VERSION 5.8 ;
BUSBITCHARS "[]" ;
DIVIDERCHAR "/" ;
UNITS
    DATABASE MICRONS 1000 ;
END UNITS

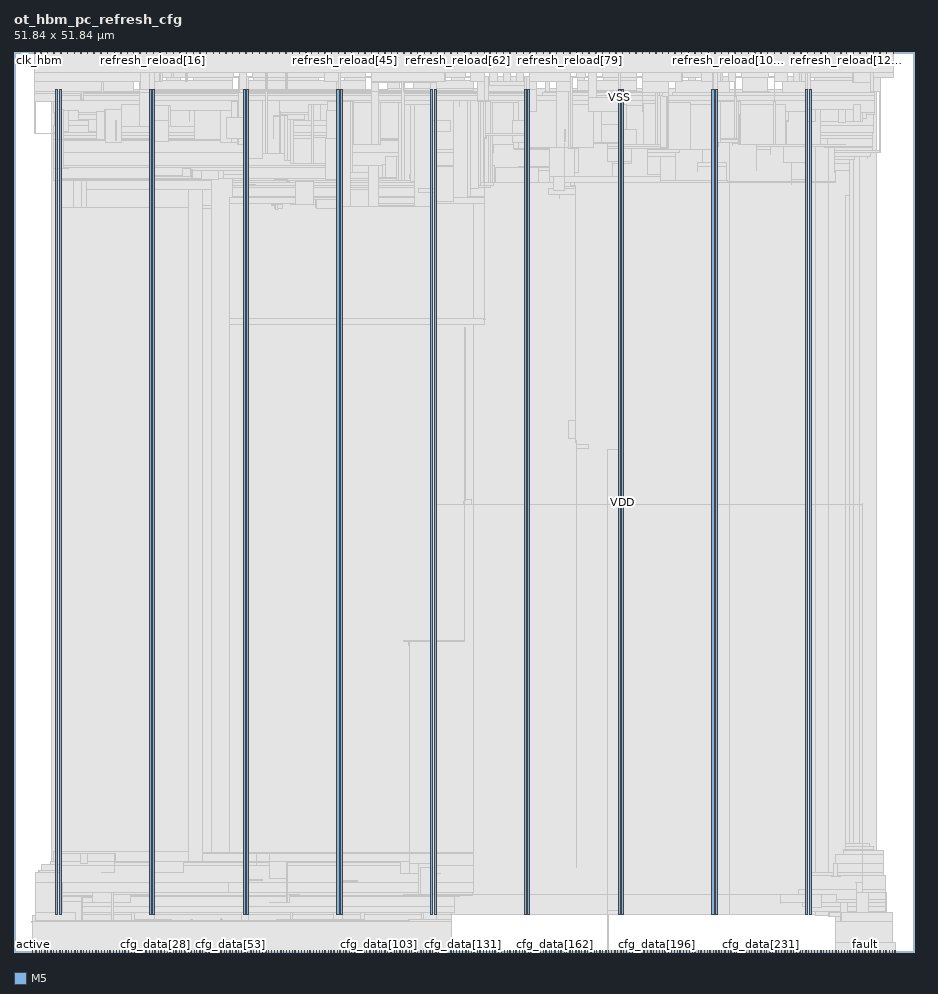
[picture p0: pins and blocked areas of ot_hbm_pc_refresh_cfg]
MACRO ot_hbm_pc_refresh_cfg
  FOREIGN ot_hbm_pc_refresh_cfg 0 0 ;
  CLASS BLOCK ;
  SIZE 51.84 BY 51.84 ;
  PIN active
    DIRECTION OUTPUT ;
    USE SIGNAL ;
    PORT
      LAYER M5 ;
        RECT  1.056 0 1.08 0.084 ;
    END
  END active
  PIN cfg_addr[0]
    DIRECTION INPUT ;
    USE SIGNAL ;
    PORT
      LAYER M5 ;
        RECT  1.248 0 1.272 0.084 ;
    END
  END cfg_addr[0]
  PIN cfg_addr[10]
    DIRECTION INPUT ;
    USE SIGNAL ;
    PORT
      LAYER M5 ;
        RECT  2.976 0 3 0.084 ;
    END
  END cfg_addr[10]
  PIN cfg_addr[11]
    DIRECTION INPUT ;
    USE SIGNAL ;
    PORT
      LAYER M5 ;
        RECT  3.12 0 3.144 0.084 ;
    END
  END cfg_addr[11]
  PIN cfg_addr[1]
    DIRECTION INPUT ;
    USE SIGNAL ;
    PORT
      LAYER M5 ;
        RECT  1.44 0 1.464 0.084 ;
    END
  END cfg_addr[1]
  PIN cfg_addr[2]
    DIRECTION INPUT ;
    USE SIGNAL ;
    PORT
      LAYER M5 ;
        RECT  1.584 0 1.608 0.084 ;
    END
  END cfg_addr[2]
  PIN cfg_addr[3]
    DIRECTION INPUT ;
    USE SIGNAL ;
    PORT
      LAYER M5 ;
        RECT  1.776 0 1.8 0.084 ;
    END
  END cfg_addr[3]
  PIN cfg_addr[4]
    DIRECTION INPUT ;
    USE SIGNAL ;
    PORT
      LAYER M5 ;
        RECT  1.92 0 1.944 0.084 ;
    END
  END cfg_addr[4]
  PIN cfg_addr[5]
    DIRECTION INPUT ;
    USE SIGNAL ;
    PORT
      LAYER M5 ;
        RECT  2.112 0 2.136 0.084 ;
    END
  END cfg_addr[5]
  PIN cfg_addr[6]
    DIRECTION INPUT ;
    USE SIGNAL ;
    PORT
      LAYER M5 ;
        RECT  2.256 0 2.28 0.084 ;
    END
  END cfg_addr[6]
  PIN cfg_addr[7]
    DIRECTION INPUT ;
    USE SIGNAL ;
    PORT
      LAYER M5 ;
        RECT  2.448 0 2.472 0.084 ;
    END
  END cfg_addr[7]
  PIN cfg_addr[8]
    DIRECTION INPUT ;
    USE SIGNAL ;
    PORT
      LAYER M5 ;
        RECT  2.64 0 2.664 0.084 ;
    END
  END cfg_addr[8]
  PIN cfg_addr[9]
    DIRECTION INPUT ;
    USE SIGNAL ;
    PORT
      LAYER M5 ;
        RECT  2.784 0 2.808 0.084 ;
    END
  END cfg_addr[9]
  PIN cfg_data[0]
    DIRECTION INPUT ;
    USE SIGNAL ;
    PORT
      LAYER M5 ;
        RECT  3.312 0 3.336 0.084 ;
    END
  END cfg_data[0]
  PIN cfg_data[100]
    DIRECTION INPUT ;
    USE SIGNAL ;
    PORT
      LAYER M5 ;
        RECT  20.496 0 20.52 0.084 ;
    END
  END cfg_data[100]
  PIN cfg_data[101]
    DIRECTION INPUT ;
    USE SIGNAL ;
    PORT
      LAYER M5 ;
        RECT  20.688 0 20.712 0.084 ;
    END
  END cfg_data[101]
  PIN cfg_data[102]
    DIRECTION INPUT ;
    USE SIGNAL ;
    PORT
      LAYER M5 ;
        RECT  20.832 0 20.856 0.084 ;
    END
  END cfg_data[102]
  PIN cfg_data[103]
    DIRECTION INPUT ;
    USE SIGNAL ;
    PORT
      LAYER M5 ;
        RECT  21.024 0 21.048 0.084 ;
    END
  END cfg_data[103]
  PIN cfg_data[104]
    DIRECTION INPUT ;
    USE SIGNAL ;
    PORT
      LAYER M5 ;
        RECT  21.168 0 21.192 0.084 ;
    END
  END cfg_data[104]
  PIN cfg_data[105]
    DIRECTION INPUT ;
    USE SIGNAL ;
    PORT
      LAYER M5 ;
        RECT  21.36 0 21.384 0.084 ;
    END
  END cfg_data[105]
  PIN cfg_data[106]
    DIRECTION INPUT ;
    USE SIGNAL ;
    PORT
      LAYER M5 ;
        RECT  21.504 0 21.528 0.084 ;
    END
  END cfg_data[106]
  PIN cfg_data[107]
    DIRECTION INPUT ;
    USE SIGNAL ;
    PORT
      LAYER M5 ;
        RECT  21.696 0 21.72 0.084 ;
    END
  END cfg_data[107]
  PIN cfg_data[108]
    DIRECTION INPUT ;
    USE SIGNAL ;
    PORT
      LAYER M5 ;
        RECT  21.888 0 21.912 0.084 ;
    END
  END cfg_data[108]
  PIN cfg_data[109]
    DIRECTION INPUT ;
    USE SIGNAL ;
    PORT
      LAYER M5 ;
        RECT  22.032 0 22.056 0.084 ;
    END
  END cfg_data[109]
  PIN cfg_data[10]
    DIRECTION INPUT ;
    USE SIGNAL ;
    PORT
      LAYER M5 ;
        RECT  5.04 0 5.064 0.084 ;
    END
  END cfg_data[10]
  PIN cfg_data[110]
    DIRECTION INPUT ;
    USE SIGNAL ;
    PORT
      LAYER M5 ;
        RECT  22.224 0 22.248 0.084 ;
    END
  END cfg_data[110]
  PIN cfg_data[111]
    DIRECTION INPUT ;
    USE SIGNAL ;
    PORT
      LAYER M5 ;
        RECT  22.368 0 22.392 0.084 ;
    END
  END cfg_data[111]
  PIN cfg_data[112]
    DIRECTION INPUT ;
    USE SIGNAL ;
    PORT
      LAYER M5 ;
        RECT  22.56 0 22.584 0.084 ;
    END
  END cfg_data[112]
  PIN cfg_data[113]
    DIRECTION INPUT ;
    USE SIGNAL ;
    PORT
      LAYER M5 ;
        RECT  22.752 0 22.776 0.084 ;
    END
  END cfg_data[113]
  PIN cfg_data[114]
    DIRECTION INPUT ;
    USE SIGNAL ;
    PORT
      LAYER M5 ;
        RECT  22.896 0 22.92 0.084 ;
    END
  END cfg_data[114]
  PIN cfg_data[115]
    DIRECTION INPUT ;
    USE SIGNAL ;
    PORT
      LAYER M5 ;
        RECT  23.088 0 23.112 0.084 ;
    END
  END cfg_data[115]
  PIN cfg_data[116]
    DIRECTION INPUT ;
    USE SIGNAL ;
    PORT
      LAYER M5 ;
        RECT  23.232 0 23.256 0.084 ;
    END
  END cfg_data[116]
  PIN cfg_data[117]
    DIRECTION INPUT ;
    USE SIGNAL ;
    PORT
      LAYER M5 ;
        RECT  23.424 0 23.448 0.084 ;
    END
  END cfg_data[117]
  PIN cfg_data[118]
    DIRECTION INPUT ;
    USE SIGNAL ;
    PORT
      LAYER M5 ;
        RECT  23.568 0 23.592 0.084 ;
    END
  END cfg_data[118]
  PIN cfg_data[119]
    DIRECTION INPUT ;
    USE SIGNAL ;
    PORT
      LAYER M5 ;
        RECT  23.76 0 23.784 0.084 ;
    END
  END cfg_data[119]
  PIN cfg_data[11]
    DIRECTION INPUT ;
    USE SIGNAL ;
    PORT
      LAYER M5 ;
        RECT  5.184 0 5.208 0.084 ;
    END
  END cfg_data[11]
  PIN cfg_data[120]
    DIRECTION INPUT ;
    USE SIGNAL ;
    PORT
      LAYER M5 ;
        RECT  23.952 0 23.976 0.084 ;
    END
  END cfg_data[120]
  PIN cfg_data[121]
    DIRECTION INPUT ;
    USE SIGNAL ;
    PORT
      LAYER M5 ;
        RECT  24.096 0 24.12 0.084 ;
    END
  END cfg_data[121]
  PIN cfg_data[122]
    DIRECTION INPUT ;
    USE SIGNAL ;
    PORT
      LAYER M5 ;
        RECT  24.288 0 24.312 0.084 ;
    END
  END cfg_data[122]
  PIN cfg_data[123]
    DIRECTION INPUT ;
    USE SIGNAL ;
    PORT
      LAYER M5 ;
        RECT  24.432 0 24.456 0.084 ;
    END
  END cfg_data[123]
  PIN cfg_data[124]
    DIRECTION INPUT ;
    USE SIGNAL ;
    PORT
      LAYER M5 ;
        RECT  24.624 0 24.648 0.084 ;
    END
  END cfg_data[124]
  PIN cfg_data[125]
    DIRECTION INPUT ;
    USE SIGNAL ;
    PORT
      LAYER M5 ;
        RECT  24.768 0 24.792 0.084 ;
    END
  END cfg_data[125]
  PIN cfg_data[126]
    DIRECTION INPUT ;
    USE SIGNAL ;
    PORT
      LAYER M5 ;
        RECT  24.96 0 24.984 0.084 ;
    END
  END cfg_data[126]
  PIN cfg_data[127]
    DIRECTION INPUT ;
    USE SIGNAL ;
    PORT
      LAYER M5 ;
        RECT  25.152 0 25.176 0.084 ;
    END
  END cfg_data[127]
  PIN cfg_data[128]
    DIRECTION INPUT ;
    USE SIGNAL ;
    PORT
      LAYER M5 ;
        RECT  25.296 0 25.32 0.084 ;
    END
  END cfg_data[128]
  PIN cfg_data[129]
    DIRECTION INPUT ;
    USE SIGNAL ;
    PORT
      LAYER M5 ;
        RECT  25.488 0 25.512 0.084 ;
    END
  END cfg_data[129]
  PIN cfg_data[12]
    DIRECTION INPUT ;
    USE SIGNAL ;
    PORT
      LAYER M5 ;
        RECT  5.376 0 5.4 0.084 ;
    END
  END cfg_data[12]
  PIN cfg_data[130]
    DIRECTION INPUT ;
    USE SIGNAL ;
    PORT
      LAYER M5 ;
        RECT  25.632 0 25.656 0.084 ;
    END
  END cfg_data[130]
  PIN cfg_data[131]
    DIRECTION INPUT ;
    USE SIGNAL ;
    PORT
      LAYER M5 ;
        RECT  25.824 0 25.848 0.084 ;
    END
  END cfg_data[131]
  PIN cfg_data[132]
    DIRECTION INPUT ;
    USE SIGNAL ;
    PORT
      LAYER M5 ;
        RECT  26.016 0 26.04 0.084 ;
    END
  END cfg_data[132]
  PIN cfg_data[133]
    DIRECTION INPUT ;
    USE SIGNAL ;
    PORT
      LAYER M5 ;
        RECT  26.16 0 26.184 0.084 ;
    END
  END cfg_data[133]
  PIN cfg_data[134]
    DIRECTION INPUT ;
    USE SIGNAL ;
    PORT
      LAYER M5 ;
        RECT  26.352 0 26.376 0.084 ;
    END
  END cfg_data[134]
  PIN cfg_data[135]
    DIRECTION INPUT ;
    USE SIGNAL ;
    PORT
      LAYER M5 ;
        RECT  26.496 0 26.52 0.084 ;
    END
  END cfg_data[135]
  PIN cfg_data[136]
    DIRECTION INPUT ;
    USE SIGNAL ;
    PORT
      LAYER M5 ;
        RECT  26.688 0 26.712 0.084 ;
    END
  END cfg_data[136]
  PIN cfg_data[137]
    DIRECTION INPUT ;
    USE SIGNAL ;
    PORT
      LAYER M5 ;
        RECT  26.832 0 26.856 0.084 ;
    END
  END cfg_data[137]
  PIN cfg_data[138]
    DIRECTION INPUT ;
    USE SIGNAL ;
    PORT
      LAYER M5 ;
        RECT  27.024 0 27.048 0.084 ;
    END
  END cfg_data[138]
  PIN cfg_data[139]
    DIRECTION INPUT ;
    USE SIGNAL ;
    PORT
      LAYER M5 ;
        RECT  27.216 0 27.24 0.084 ;
    END
  END cfg_data[139]
  PIN cfg_data[13]
    DIRECTION INPUT ;
    USE SIGNAL ;
    PORT
      LAYER M5 ;
        RECT  5.52 0 5.544 0.084 ;
    END
  END cfg_data[13]
  PIN cfg_data[140]
    DIRECTION INPUT ;
    USE SIGNAL ;
    PORT
      LAYER M5 ;
        RECT  27.36 0 27.384 0.084 ;
    END
  END cfg_data[140]
  PIN cfg_data[141]
    DIRECTION INPUT ;
    USE SIGNAL ;
    PORT
      LAYER M5 ;
        RECT  27.552 0 27.576 0.084 ;
    END
  END cfg_data[141]
  PIN cfg_data[142]
    DIRECTION INPUT ;
    USE SIGNAL ;
    PORT
      LAYER M5 ;
        RECT  27.696 0 27.72 0.084 ;
    END
  END cfg_data[142]
  PIN cfg_data[143]
    DIRECTION INPUT ;
    USE SIGNAL ;
    PORT
      LAYER M5 ;
        RECT  27.888 0 27.912 0.084 ;
    END
  END cfg_data[143]
  PIN cfg_data[144]
    DIRECTION INPUT ;
    USE SIGNAL ;
    PORT
      LAYER M5 ;
        RECT  28.08 0 28.104 0.084 ;
    END
  END cfg_data[144]
  PIN cfg_data[145]
    DIRECTION INPUT ;
    USE SIGNAL ;
    PORT
      LAYER M5 ;
        RECT  28.224 0 28.248 0.084 ;
    END
  END cfg_data[145]
  PIN cfg_data[146]
    DIRECTION INPUT ;
    USE SIGNAL ;
    PORT
      LAYER M5 ;
        RECT  28.416 0 28.44 0.084 ;
    END
  END cfg_data[146]
  PIN cfg_data[147]
    DIRECTION INPUT ;
    USE SIGNAL ;
    PORT
      LAYER M5 ;
        RECT  28.56 0 28.584 0.084 ;
    END
  END cfg_data[147]
  PIN cfg_data[148]
    DIRECTION INPUT ;
    USE SIGNAL ;
    PORT
      LAYER M5 ;
        RECT  28.752 0 28.776 0.084 ;
    END
  END cfg_data[148]
  PIN cfg_data[149]
    DIRECTION INPUT ;
    USE SIGNAL ;
    PORT
      LAYER M5 ;
        RECT  28.896 0 28.92 0.084 ;
    END
  END cfg_data[149]
  PIN cfg_data[14]
    DIRECTION INPUT ;
    USE SIGNAL ;
    PORT
      LAYER M5 ;
        RECT  5.712 0 5.736 0.084 ;
    END
  END cfg_data[14]
  PIN cfg_data[150]
    DIRECTION INPUT ;
    USE SIGNAL ;
    PORT
      LAYER M5 ;
        RECT  29.088 0 29.112 0.084 ;
    END
  END cfg_data[150]
  PIN cfg_data[151]
    DIRECTION INPUT ;
    USE SIGNAL ;
    PORT
      LAYER M5 ;
        RECT  29.28 0 29.304 0.084 ;
    END
  END cfg_data[151]
  PIN cfg_data[152]
    DIRECTION INPUT ;
    USE SIGNAL ;
    PORT
      LAYER M5 ;
        RECT  29.424 0 29.448 0.084 ;
    END
  END cfg_data[152]
  PIN cfg_data[153]
    DIRECTION INPUT ;
    USE SIGNAL ;
    PORT
      LAYER M5 ;
        RECT  29.616 0 29.64 0.084 ;
    END
  END cfg_data[153]
  PIN cfg_data[154]
    DIRECTION INPUT ;
    USE SIGNAL ;
    PORT
      LAYER M5 ;
        RECT  29.76 0 29.784 0.084 ;
    END
  END cfg_data[154]
  PIN cfg_data[155]
    DIRECTION INPUT ;
    USE SIGNAL ;
    PORT
      LAYER M5 ;
        RECT  29.952 0 29.976 0.084 ;
    END
  END cfg_data[155]
  PIN cfg_data[156]
    DIRECTION INPUT ;
    USE SIGNAL ;
    PORT
      LAYER M5 ;
        RECT  30.096 0 30.12 0.084 ;
    END
  END cfg_data[156]
  PIN cfg_data[157]
    DIRECTION INPUT ;
    USE SIGNAL ;
    PORT
      LAYER M5 ;
        RECT  30.288 0 30.312 0.084 ;
    END
  END cfg_data[157]
  PIN cfg_data[158]
    DIRECTION INPUT ;
    USE SIGNAL ;
    PORT
      LAYER M5 ;
        RECT  30.48 0 30.504 0.084 ;
    END
  END cfg_data[158]
  PIN cfg_data[159]
    DIRECTION INPUT ;
    USE SIGNAL ;
    PORT
      LAYER M5 ;
        RECT  30.624 0 30.648 0.084 ;
    END
  END cfg_data[159]
  PIN cfg_data[15]
    DIRECTION INPUT ;
    USE SIGNAL ;
    PORT
      LAYER M5 ;
        RECT  5.904 0 5.928 0.084 ;
    END
  END cfg_data[15]
  PIN cfg_data[160]
    DIRECTION INPUT ;
    USE SIGNAL ;
    PORT
      LAYER M5 ;
        RECT  30.816 0 30.84 0.084 ;
    END
  END cfg_data[160]
  PIN cfg_data[161]
    DIRECTION INPUT ;
    USE SIGNAL ;
    PORT
      LAYER M5 ;
        RECT  30.96 0 30.984 0.084 ;
    END
  END cfg_data[161]
  PIN cfg_data[162]
    DIRECTION INPUT ;
    USE SIGNAL ;
    PORT
      LAYER M5 ;
        RECT  31.152 0 31.176 0.084 ;
    END
  END cfg_data[162]
  PIN cfg_data[163]
    DIRECTION INPUT ;
    USE SIGNAL ;
    PORT
      LAYER M5 ;
        RECT  31.344 0 31.368 0.084 ;
    END
  END cfg_data[163]
  PIN cfg_data[164]
    DIRECTION INPUT ;
    USE SIGNAL ;
    PORT
      LAYER M5 ;
        RECT  31.488 0 31.512 0.084 ;
    END
  END cfg_data[164]
  PIN cfg_data[165]
    DIRECTION INPUT ;
    USE SIGNAL ;
    PORT
      LAYER M5 ;
        RECT  31.68 0 31.704 0.084 ;
    END
  END cfg_data[165]
  PIN cfg_data[166]
    DIRECTION INPUT ;
    USE SIGNAL ;
    PORT
      LAYER M5 ;
        RECT  31.824 0 31.848 0.084 ;
    END
  END cfg_data[166]
  PIN cfg_data[167]
    DIRECTION INPUT ;
    USE SIGNAL ;
    PORT
      LAYER M5 ;
        RECT  32.016 0 32.04 0.084 ;
    END
  END cfg_data[167]
  PIN cfg_data[168]
    DIRECTION INPUT ;
    USE SIGNAL ;
    PORT
      LAYER M5 ;
        RECT  32.16 0 32.184 0.084 ;
    END
  END cfg_data[168]
  PIN cfg_data[169]
    DIRECTION INPUT ;
    USE SIGNAL ;
    PORT
      LAYER M5 ;
        RECT  32.352 0 32.376 0.084 ;
    END
  END cfg_data[169]
  PIN cfg_data[16]
    DIRECTION INPUT ;
    USE SIGNAL ;
    PORT
      LAYER M5 ;
        RECT  6.048 0 6.072 0.084 ;
    END
  END cfg_data[16]
  PIN cfg_data[170]
    DIRECTION INPUT ;
    USE SIGNAL ;
    PORT
      LAYER M5 ;
        RECT  32.544 0 32.568 0.084 ;
    END
  END cfg_data[170]
  PIN cfg_data[171]
    DIRECTION INPUT ;
    USE SIGNAL ;
    PORT
      LAYER M5 ;
        RECT  32.688 0 32.712 0.084 ;
    END
  END cfg_data[171]
  PIN cfg_data[172]
    DIRECTION INPUT ;
    USE SIGNAL ;
    PORT
      LAYER M5 ;
        RECT  32.88 0 32.904 0.084 ;
    END
  END cfg_data[172]
  PIN cfg_data[173]
    DIRECTION INPUT ;
    USE SIGNAL ;
    PORT
      LAYER M5 ;
        RECT  33.024 0 33.048 0.084 ;
    END
  END cfg_data[173]
  PIN cfg_data[174]
    DIRECTION INPUT ;
    USE SIGNAL ;
    PORT
      LAYER M5 ;
        RECT  33.216 0 33.24 0.084 ;
    END
  END cfg_data[174]
  PIN cfg_data[175]
    DIRECTION INPUT ;
    USE SIGNAL ;
    PORT
      LAYER M5 ;
        RECT  33.408 0 33.432 0.084 ;
    END
  END cfg_data[175]
  PIN cfg_data[176]
    DIRECTION INPUT ;
    USE SIGNAL ;
    PORT
      LAYER M5 ;
        RECT  33.552 0 33.576 0.084 ;
    END
  END cfg_data[176]
  PIN cfg_data[177]
    DIRECTION INPUT ;
    USE SIGNAL ;
    PORT
      LAYER M5 ;
        RECT  33.744 0 33.768 0.084 ;
    END
  END cfg_data[177]
  PIN cfg_data[178]
    DIRECTION INPUT ;
    USE SIGNAL ;
    PORT
      LAYER M5 ;
        RECT  33.888 0 33.912 0.084 ;
    END
  END cfg_data[178]
  PIN cfg_data[179]
    DIRECTION INPUT ;
    USE SIGNAL ;
    PORT
      LAYER M5 ;
        RECT  34.08 0 34.104 0.084 ;
    END
  END cfg_data[179]
  PIN cfg_data[17]
    DIRECTION INPUT ;
    USE SIGNAL ;
    PORT
      LAYER M5 ;
        RECT  6.24 0 6.264 0.084 ;
    END
  END cfg_data[17]
  PIN cfg_data[180]
    DIRECTION INPUT ;
    USE SIGNAL ;
    PORT
      LAYER M5 ;
        RECT  34.224 0 34.248 0.084 ;
    END
  END cfg_data[180]
  PIN cfg_data[181]
    DIRECTION INPUT ;
    USE SIGNAL ;
    PORT
      LAYER M5 ;
        RECT  34.416 0 34.44 0.084 ;
    END
  END cfg_data[181]
  PIN cfg_data[182]
    DIRECTION INPUT ;
    USE SIGNAL ;
    PORT
      LAYER M5 ;
        RECT  34.608 0 34.632 0.084 ;
    END
  END cfg_data[182]
  PIN cfg_data[183]
    DIRECTION INPUT ;
    USE SIGNAL ;
    PORT
      LAYER M5 ;
        RECT  34.752 0 34.776 0.084 ;
    END
  END cfg_data[183]
  PIN cfg_data[184]
    DIRECTION INPUT ;
    USE SIGNAL ;
    PORT
      LAYER M5 ;
        RECT  34.944 0 34.968 0.084 ;
    END
  END cfg_data[184]
  PIN cfg_data[185]
    DIRECTION INPUT ;
    USE SIGNAL ;
    PORT
      LAYER M5 ;
        RECT  35.088 0 35.112 0.084 ;
    END
  END cfg_data[185]
  PIN cfg_data[186]
    DIRECTION INPUT ;
    USE SIGNAL ;
    PORT
      LAYER M5 ;
        RECT  35.28 0 35.304 0.084 ;
    END
  END cfg_data[186]
  PIN cfg_data[187]
    DIRECTION INPUT ;
    USE SIGNAL ;
    PORT
      LAYER M5 ;
        RECT  35.424 0 35.448 0.084 ;
    END
  END cfg_data[187]
  PIN cfg_data[188]
    DIRECTION INPUT ;
    USE SIGNAL ;
    PORT
      LAYER M5 ;
        RECT  35.616 0 35.64 0.084 ;
    END
  END cfg_data[188]
  PIN cfg_data[189]
    DIRECTION INPUT ;
    USE SIGNAL ;
    PORT
      LAYER M5 ;
        RECT  35.808 0 35.832 0.084 ;
    END
  END cfg_data[189]
  PIN cfg_data[18]
    DIRECTION INPUT ;
    USE SIGNAL ;
    PORT
      LAYER M5 ;
        RECT  6.384 0 6.408 0.084 ;
    END
  END cfg_data[18]
  PIN cfg_data[190]
    DIRECTION INPUT ;
    USE SIGNAL ;
    PORT
      LAYER M5 ;
        RECT  35.952 0 35.976 0.084 ;
    END
  END cfg_data[190]
  PIN cfg_data[191]
    DIRECTION INPUT ;
    USE SIGNAL ;
    PORT
      LAYER M5 ;
        RECT  36.144 0 36.168 0.084 ;
    END
  END cfg_data[191]
  PIN cfg_data[192]
    DIRECTION INPUT ;
    USE SIGNAL ;
    PORT
      LAYER M5 ;
        RECT  36.288 0 36.312 0.084 ;
    END
  END cfg_data[192]
  PIN cfg_data[193]
    DIRECTION INPUT ;
    USE SIGNAL ;
    PORT
      LAYER M5 ;
        RECT  36.48 0 36.504 0.084 ;
    END
  END cfg_data[193]
  PIN cfg_data[194]
    DIRECTION INPUT ;
    USE SIGNAL ;
    PORT
      LAYER M5 ;
        RECT  36.672 0 36.696 0.084 ;
    END
  END cfg_data[194]
  PIN cfg_data[195]
    DIRECTION INPUT ;
    USE SIGNAL ;
    PORT
      LAYER M5 ;
        RECT  36.816 0 36.84 0.084 ;
    END
  END cfg_data[195]
  PIN cfg_data[196]
    DIRECTION INPUT ;
    USE SIGNAL ;
    PORT
      LAYER M5 ;
        RECT  37.008 0 37.032 0.084 ;
    END
  END cfg_data[196]
  PIN cfg_data[197]
    DIRECTION INPUT ;
    USE SIGNAL ;
    PORT
      LAYER M5 ;
        RECT  37.152 0 37.176 0.084 ;
    END
  END cfg_data[197]
  PIN cfg_data[198]
    DIRECTION INPUT ;
    USE SIGNAL ;
    PORT
      LAYER M5 ;
        RECT  37.344 0 37.368 0.084 ;
    END
  END cfg_data[198]
  PIN cfg_data[199]
    DIRECTION INPUT ;
    USE SIGNAL ;
    PORT
      LAYER M5 ;
        RECT  37.488 0 37.512 0.084 ;
    END
  END cfg_data[199]
  PIN cfg_data[19]
    DIRECTION INPUT ;
    USE SIGNAL ;
    PORT
      LAYER M5 ;
        RECT  6.576 0 6.6 0.084 ;
    END
  END cfg_data[19]
  PIN cfg_data[1]
    DIRECTION INPUT ;
    USE SIGNAL ;
    PORT
      LAYER M5 ;
        RECT  3.504 0 3.528 0.084 ;
    END
  END cfg_data[1]
  PIN cfg_data[200]
    DIRECTION INPUT ;
    USE SIGNAL ;
    PORT
      LAYER M5 ;
        RECT  37.68 0 37.704 0.084 ;
    END
  END cfg_data[200]
  PIN cfg_data[201]
    DIRECTION INPUT ;
    USE SIGNAL ;
    PORT
      LAYER M5 ;
        RECT  37.872 0 37.896 0.084 ;
    END
  END cfg_data[201]
  PIN cfg_data[202]
    DIRECTION INPUT ;
    USE SIGNAL ;
    PORT
      LAYER M5 ;
        RECT  38.016 0 38.04 0.084 ;
    END
  END cfg_data[202]
  PIN cfg_data[203]
    DIRECTION INPUT ;
    USE SIGNAL ;
    PORT
      LAYER M5 ;
        RECT  38.208 0 38.232 0.084 ;
    END
  END cfg_data[203]
  PIN cfg_data[204]
    DIRECTION INPUT ;
    USE SIGNAL ;
    PORT
      LAYER M5 ;
        RECT  38.352 0 38.376 0.084 ;
    END
  END cfg_data[204]
  PIN cfg_data[205]
    DIRECTION INPUT ;
    USE SIGNAL ;
    PORT
      LAYER M5 ;
        RECT  38.544 0 38.568 0.084 ;
    END
  END cfg_data[205]
  PIN cfg_data[206]
    DIRECTION INPUT ;
    USE SIGNAL ;
    PORT
      LAYER M5 ;
        RECT  38.736 0 38.76 0.084 ;
    END
  END cfg_data[206]
  PIN cfg_data[207]
    DIRECTION INPUT ;
    USE SIGNAL ;
    PORT
      LAYER M5 ;
        RECT  38.88 0 38.904 0.084 ;
    END
  END cfg_data[207]
  PIN cfg_data[208]
    DIRECTION INPUT ;
    USE SIGNAL ;
    PORT
      LAYER M5 ;
        RECT  39.072 0 39.096 0.084 ;
    END
  END cfg_data[208]
  PIN cfg_data[209]
    DIRECTION INPUT ;
    USE SIGNAL ;
    PORT
      LAYER M5 ;
        RECT  39.216 0 39.24 0.084 ;
    END
  END cfg_data[209]
  PIN cfg_data[20]
    DIRECTION INPUT ;
    USE SIGNAL ;
    PORT
      LAYER M5 ;
        RECT  6.768 0 6.792 0.084 ;
    END
  END cfg_data[20]
  PIN cfg_data[210]
    DIRECTION INPUT ;
    USE SIGNAL ;
    PORT
      LAYER M5 ;
        RECT  39.408 0 39.432 0.084 ;
    END
  END cfg_data[210]
  PIN cfg_data[211]
    DIRECTION INPUT ;
    USE SIGNAL ;
    PORT
      LAYER M5 ;
        RECT  39.552 0 39.576 0.084 ;
    END
  END cfg_data[211]
  PIN cfg_data[212]
    DIRECTION INPUT ;
    USE SIGNAL ;
    PORT
      LAYER M5 ;
        RECT  39.744 0 39.768 0.084 ;
    END
  END cfg_data[212]
  PIN cfg_data[213]
    DIRECTION INPUT ;
    USE SIGNAL ;
    PORT
      LAYER M5 ;
        RECT  39.936 0 39.96 0.084 ;
    END
  END cfg_data[213]
  PIN cfg_data[214]
    DIRECTION INPUT ;
    USE SIGNAL ;
    PORT
      LAYER M5 ;
        RECT  40.08 0 40.104 0.084 ;
    END
  END cfg_data[214]
  PIN cfg_data[215]
    DIRECTION INPUT ;
    USE SIGNAL ;
    PORT
      LAYER M5 ;
        RECT  40.272 0 40.296 0.084 ;
    END
  END cfg_data[215]
  PIN cfg_data[216]
    DIRECTION INPUT ;
    USE SIGNAL ;
    PORT
      LAYER M5 ;
        RECT  40.416 0 40.44 0.084 ;
    END
  END cfg_data[216]
  PIN cfg_data[217]
    DIRECTION INPUT ;
    USE SIGNAL ;
    PORT
      LAYER M5 ;
        RECT  40.608 0 40.632 0.084 ;
    END
  END cfg_data[217]
  PIN cfg_data[218]
    DIRECTION INPUT ;
    USE SIGNAL ;
    PORT
      LAYER M5 ;
        RECT  40.752 0 40.776 0.084 ;
    END
  END cfg_data[218]
  PIN cfg_data[219]
    DIRECTION INPUT ;
    USE SIGNAL ;
    PORT
      LAYER M5 ;
        RECT  40.944 0 40.968 0.084 ;
    END
  END cfg_data[219]
  PIN cfg_data[21]
    DIRECTION INPUT ;
    USE SIGNAL ;
    PORT
      LAYER M5 ;
        RECT  6.912 0 6.936 0.084 ;
    END
  END cfg_data[21]
  PIN cfg_data[220]
    DIRECTION INPUT ;
    USE SIGNAL ;
    PORT
      LAYER M5 ;
        RECT  41.136 0 41.16 0.084 ;
    END
  END cfg_data[220]
  PIN cfg_data[221]
    DIRECTION INPUT ;
    USE SIGNAL ;
    PORT
      LAYER M5 ;
        RECT  41.28 0 41.304 0.084 ;
    END
  END cfg_data[221]
  PIN cfg_data[222]
    DIRECTION INPUT ;
    USE SIGNAL ;
    PORT
      LAYER M5 ;
        RECT  41.472 0 41.496 0.084 ;
    END
  END cfg_data[222]
  PIN cfg_data[223]
    DIRECTION INPUT ;
    USE SIGNAL ;
    PORT
      LAYER M5 ;
        RECT  41.616 0 41.64 0.084 ;
    END
  END cfg_data[223]
  PIN cfg_data[224]
    DIRECTION INPUT ;
    USE SIGNAL ;
    PORT
      LAYER M5 ;
        RECT  41.808 0 41.832 0.084 ;
    END
  END cfg_data[224]
  PIN cfg_data[225]
    DIRECTION INPUT ;
    USE SIGNAL ;
    PORT
      LAYER M5 ;
        RECT  42 0 42.024 0.084 ;
    END
  END cfg_data[225]
  PIN cfg_data[226]
    DIRECTION INPUT ;
    USE SIGNAL ;
    PORT
      LAYER M5 ;
        RECT  42.144 0 42.168 0.084 ;
    END
  END cfg_data[226]
  PIN cfg_data[227]
    DIRECTION INPUT ;
    USE SIGNAL ;
    PORT
      LAYER M5 ;
        RECT  42.336 0 42.36 0.084 ;
    END
  END cfg_data[227]
  PIN cfg_data[228]
    DIRECTION INPUT ;
    USE SIGNAL ;
    PORT
      LAYER M5 ;
        RECT  42.48 0 42.504 0.084 ;
    END
  END cfg_data[228]
  PIN cfg_data[229]
    DIRECTION INPUT ;
    USE SIGNAL ;
    PORT
      LAYER M5 ;
        RECT  42.672 0 42.696 0.084 ;
    END
  END cfg_data[229]
  PIN cfg_data[22]
    DIRECTION INPUT ;
    USE SIGNAL ;
    PORT
      LAYER M5 ;
        RECT  7.104 0 7.128 0.084 ;
    END
  END cfg_data[22]
  PIN cfg_data[230]
    DIRECTION INPUT ;
    USE SIGNAL ;
    PORT
      LAYER M5 ;
        RECT  42.816 0 42.84 0.084 ;
    END
  END cfg_data[230]
  PIN cfg_data[231]
    DIRECTION INPUT ;
    USE SIGNAL ;
    PORT
      LAYER M5 ;
        RECT  43.008 0 43.032 0.084 ;
    END
  END cfg_data[231]
  PIN cfg_data[232]
    DIRECTION INPUT ;
    USE SIGNAL ;
    PORT
      LAYER M5 ;
        RECT  43.2 0 43.224 0.084 ;
    END
  END cfg_data[232]
  PIN cfg_data[233]
    DIRECTION INPUT ;
    USE SIGNAL ;
    PORT
      LAYER M5 ;
        RECT  43.344 0 43.368 0.084 ;
    END
  END cfg_data[233]
  PIN cfg_data[234]
    DIRECTION INPUT ;
    USE SIGNAL ;
    PORT
      LAYER M5 ;
        RECT  43.536 0 43.56 0.084 ;
    END
  END cfg_data[234]
  PIN cfg_data[235]
    DIRECTION INPUT ;
    USE SIGNAL ;
    PORT
      LAYER M5 ;
        RECT  43.68 0 43.704 0.084 ;
    END
  END cfg_data[235]
  PIN cfg_data[236]
    DIRECTION INPUT ;
    USE SIGNAL ;
    PORT
      LAYER M5 ;
        RECT  43.872 0 43.896 0.084 ;
    END
  END cfg_data[236]
  PIN cfg_data[237]
    DIRECTION INPUT ;
    USE SIGNAL ;
    PORT
      LAYER M5 ;
        RECT  44.016 0 44.04 0.084 ;
    END
  END cfg_data[237]
  PIN cfg_data[238]
    DIRECTION INPUT ;
    USE SIGNAL ;
    PORT
      LAYER M5 ;
        RECT  44.208 0 44.232 0.084 ;
    END
  END cfg_data[238]
  PIN cfg_data[239]
    DIRECTION INPUT ;
    USE SIGNAL ;
    PORT
      LAYER M5 ;
        RECT  44.4 0 44.424 0.084 ;
    END
  END cfg_data[239]
  PIN cfg_data[23]
    DIRECTION INPUT ;
    USE SIGNAL ;
    PORT
      LAYER M5 ;
        RECT  7.248 0 7.272 0.084 ;
    END
  END cfg_data[23]
  PIN cfg_data[240]
    DIRECTION INPUT ;
    USE SIGNAL ;
    PORT
      LAYER M5 ;
        RECT  44.544 0 44.568 0.084 ;
    END
  END cfg_data[240]
  PIN cfg_data[241]
    DIRECTION INPUT ;
    USE SIGNAL ;
    PORT
      LAYER M5 ;
        RECT  44.736 0 44.76 0.084 ;
    END
  END cfg_data[241]
  PIN cfg_data[242]
    DIRECTION INPUT ;
    USE SIGNAL ;
    PORT
      LAYER M5 ;
        RECT  44.88 0 44.904 0.084 ;
    END
  END cfg_data[242]
  PIN cfg_data[243]
    DIRECTION INPUT ;
    USE SIGNAL ;
    PORT
      LAYER M5 ;
        RECT  45.072 0 45.096 0.084 ;
    END
  END cfg_data[243]
  PIN cfg_data[244]
    DIRECTION INPUT ;
    USE SIGNAL ;
    PORT
      LAYER M5 ;
        RECT  45.264 0 45.288 0.084 ;
    END
  END cfg_data[244]
  PIN cfg_data[245]
    DIRECTION INPUT ;
    USE SIGNAL ;
    PORT
      LAYER M5 ;
        RECT  45.408 0 45.432 0.084 ;
    END
  END cfg_data[245]
  PIN cfg_data[246]
    DIRECTION INPUT ;
    USE SIGNAL ;
    PORT
      LAYER M5 ;
        RECT  45.6 0 45.624 0.084 ;
    END
  END cfg_data[246]
  PIN cfg_data[247]
    DIRECTION INPUT ;
    USE SIGNAL ;
    PORT
      LAYER M5 ;
        RECT  45.744 0 45.768 0.084 ;
    END
  END cfg_data[247]
  PIN cfg_data[248]
    DIRECTION INPUT ;
    USE SIGNAL ;
    PORT
      LAYER M5 ;
        RECT  45.936 0 45.96 0.084 ;
    END
  END cfg_data[248]
  PIN cfg_data[249]
    DIRECTION INPUT ;
    USE SIGNAL ;
    PORT
      LAYER M5 ;
        RECT  46.08 0 46.104 0.084 ;
    END
  END cfg_data[249]
  PIN cfg_data[24]
    DIRECTION INPUT ;
    USE SIGNAL ;
    PORT
      LAYER M5 ;
        RECT  7.44 0 7.464 0.084 ;
    END
  END cfg_data[24]
  PIN cfg_data[250]
    DIRECTION INPUT ;
    USE SIGNAL ;
    PORT
      LAYER M5 ;
        RECT  46.272 0 46.296 0.084 ;
    END
  END cfg_data[250]
  PIN cfg_data[251]
    DIRECTION INPUT ;
    USE SIGNAL ;
    PORT
      LAYER M5 ;
        RECT  46.464 0 46.488 0.084 ;
    END
  END cfg_data[251]
  PIN cfg_data[252]
    DIRECTION INPUT ;
    USE SIGNAL ;
    PORT
      LAYER M5 ;
        RECT  46.608 0 46.632 0.084 ;
    END
  END cfg_data[252]
  PIN cfg_data[253]
    DIRECTION INPUT ;
    USE SIGNAL ;
    PORT
      LAYER M5 ;
        RECT  46.8 0 46.824 0.084 ;
    END
  END cfg_data[253]
  PIN cfg_data[254]
    DIRECTION INPUT ;
    USE SIGNAL ;
    PORT
      LAYER M5 ;
        RECT  46.944 0 46.968 0.084 ;
    END
  END cfg_data[254]
  PIN cfg_data[255]
    DIRECTION INPUT ;
    USE SIGNAL ;
    PORT
      LAYER M5 ;
        RECT  47.136 0 47.16 0.084 ;
    END
  END cfg_data[255]
  PIN cfg_data[25]
    DIRECTION INPUT ;
    USE SIGNAL ;
    PORT
      LAYER M5 ;
        RECT  7.584 0 7.608 0.084 ;
    END
  END cfg_data[25]
  PIN cfg_data[26]
    DIRECTION INPUT ;
    USE SIGNAL ;
    PORT
      LAYER M5 ;
        RECT  7.776 0 7.8 0.084 ;
    END
  END cfg_data[26]
  PIN cfg_data[27]
    DIRECTION INPUT ;
    USE SIGNAL ;
    PORT
      LAYER M5 ;
        RECT  7.968 0 7.992 0.084 ;
    END
  END cfg_data[27]
  PIN cfg_data[28]
    DIRECTION INPUT ;
    USE SIGNAL ;
    PORT
      LAYER M5 ;
        RECT  8.112 0 8.136 0.084 ;
    END
  END cfg_data[28]
  PIN cfg_data[29]
    DIRECTION INPUT ;
    USE SIGNAL ;
    PORT
      LAYER M5 ;
        RECT  8.304 0 8.328 0.084 ;
    END
  END cfg_data[29]
  PIN cfg_data[2]
    DIRECTION INPUT ;
    USE SIGNAL ;
    PORT
      LAYER M5 ;
        RECT  3.648 0 3.672 0.084 ;
    END
  END cfg_data[2]
  PIN cfg_data[30]
    DIRECTION INPUT ;
    USE SIGNAL ;
    PORT
      LAYER M5 ;
        RECT  8.448 0 8.472 0.084 ;
    END
  END cfg_data[30]
  PIN cfg_data[31]
    DIRECTION INPUT ;
    USE SIGNAL ;
    PORT
      LAYER M5 ;
        RECT  8.64 0 8.664 0.084 ;
    END
  END cfg_data[31]
  PIN cfg_data[32]
    DIRECTION INPUT ;
    USE SIGNAL ;
    PORT
      LAYER M5 ;
        RECT  8.832 0 8.856 0.084 ;
    END
  END cfg_data[32]
  PIN cfg_data[33]
    DIRECTION INPUT ;
    USE SIGNAL ;
    PORT
      LAYER M5 ;
        RECT  8.976 0 9 0.084 ;
    END
  END cfg_data[33]
  PIN cfg_data[34]
    DIRECTION INPUT ;
    USE SIGNAL ;
    PORT
      LAYER M5 ;
        RECT  9.168 0 9.192 0.084 ;
    END
  END cfg_data[34]
  PIN cfg_data[35]
    DIRECTION INPUT ;
    USE SIGNAL ;
    PORT
      LAYER M5 ;
        RECT  9.312 0 9.336 0.084 ;
    END
  END cfg_data[35]
  PIN cfg_data[36]
    DIRECTION INPUT ;
    USE SIGNAL ;
    PORT
      LAYER M5 ;
        RECT  9.504 0 9.528 0.084 ;
    END
  END cfg_data[36]
  PIN cfg_data[37]
    DIRECTION INPUT ;
    USE SIGNAL ;
    PORT
      LAYER M5 ;
        RECT  9.648 0 9.672 0.084 ;
    END
  END cfg_data[37]
  PIN cfg_data[38]
    DIRECTION INPUT ;
    USE SIGNAL ;
    PORT
      LAYER M5 ;
        RECT  9.84 0 9.864 0.084 ;
    END
  END cfg_data[38]
  PIN cfg_data[39]
    DIRECTION INPUT ;
    USE SIGNAL ;
    PORT
      LAYER M5 ;
        RECT  10.032 0 10.056 0.084 ;
    END
  END cfg_data[39]
  PIN cfg_data[3]
    DIRECTION INPUT ;
    USE SIGNAL ;
    PORT
      LAYER M5 ;
        RECT  3.84 0 3.864 0.084 ;
    END
  END cfg_data[3]
  PIN cfg_data[40]
    DIRECTION INPUT ;
    USE SIGNAL ;
    PORT
      LAYER M5 ;
        RECT  10.176 0 10.2 0.084 ;
    END
  END cfg_data[40]
  PIN cfg_data[41]
    DIRECTION INPUT ;
    USE SIGNAL ;
    PORT
      LAYER M5 ;
        RECT  10.368 0 10.392 0.084 ;
    END
  END cfg_data[41]
  PIN cfg_data[42]
    DIRECTION INPUT ;
    USE SIGNAL ;
    PORT
      LAYER M5 ;
        RECT  10.512 0 10.536 0.084 ;
    END
  END cfg_data[42]
  PIN cfg_data[43]
    DIRECTION INPUT ;
    USE SIGNAL ;
    PORT
      LAYER M5 ;
        RECT  10.704 0 10.728 0.084 ;
    END
  END cfg_data[43]
  PIN cfg_data[44]
    DIRECTION INPUT ;
    USE SIGNAL ;
    PORT
      LAYER M5 ;
        RECT  10.848 0 10.872 0.084 ;
    END
  END cfg_data[44]
  PIN cfg_data[45]
    DIRECTION INPUT ;
    USE SIGNAL ;
    PORT
      LAYER M5 ;
        RECT  11.04 0 11.064 0.084 ;
    END
  END cfg_data[45]
  PIN cfg_data[46]
    DIRECTION INPUT ;
    USE SIGNAL ;
    PORT
      LAYER M5 ;
        RECT  11.232 0 11.256 0.084 ;
    END
  END cfg_data[46]
  PIN cfg_data[47]
    DIRECTION INPUT ;
    USE SIGNAL ;
    PORT
      LAYER M5 ;
        RECT  11.376 0 11.4 0.084 ;
    END
  END cfg_data[47]
  PIN cfg_data[48]
    DIRECTION INPUT ;
    USE SIGNAL ;
    PORT
      LAYER M5 ;
        RECT  11.568 0 11.592 0.084 ;
    END
  END cfg_data[48]
  PIN cfg_data[49]
    DIRECTION INPUT ;
    USE SIGNAL ;
    PORT
      LAYER M5 ;
        RECT  11.712 0 11.736 0.084 ;
    END
  END cfg_data[49]
  PIN cfg_data[4]
    DIRECTION INPUT ;
    USE SIGNAL ;
    PORT
      LAYER M5 ;
        RECT  3.984 0 4.008 0.084 ;
    END
  END cfg_data[4]
  PIN cfg_data[50]
    DIRECTION INPUT ;
    USE SIGNAL ;
    PORT
      LAYER M5 ;
        RECT  11.904 0 11.928 0.084 ;
    END
  END cfg_data[50]
  PIN cfg_data[51]
    DIRECTION INPUT ;
    USE SIGNAL ;
    PORT
      LAYER M5 ;
        RECT  12.096 0 12.12 0.084 ;
    END
  END cfg_data[51]
  PIN cfg_data[52]
    DIRECTION INPUT ;
    USE SIGNAL ;
    PORT
      LAYER M5 ;
        RECT  12.24 0 12.264 0.084 ;
    END
  END cfg_data[52]
  PIN cfg_data[53]
    DIRECTION INPUT ;
    USE SIGNAL ;
    PORT
      LAYER M5 ;
        RECT  12.432 0 12.456 0.084 ;
    END
  END cfg_data[53]
  PIN cfg_data[54]
    DIRECTION INPUT ;
    USE SIGNAL ;
    PORT
      LAYER M5 ;
        RECT  12.576 0 12.6 0.084 ;
    END
  END cfg_data[54]
  PIN cfg_data[55]
    DIRECTION INPUT ;
    USE SIGNAL ;
    PORT
      LAYER M5 ;
        RECT  12.768 0 12.792 0.084 ;
    END
  END cfg_data[55]
  PIN cfg_data[56]
    DIRECTION INPUT ;
    USE SIGNAL ;
    PORT
      LAYER M5 ;
        RECT  12.912 0 12.936 0.084 ;
    END
  END cfg_data[56]
  PIN cfg_data[57]
    DIRECTION INPUT ;
    USE SIGNAL ;
    PORT
      LAYER M5 ;
        RECT  13.104 0 13.128 0.084 ;
    END
  END cfg_data[57]
  PIN cfg_data[58]
    DIRECTION INPUT ;
    USE SIGNAL ;
    PORT
      LAYER M5 ;
        RECT  13.296 0 13.32 0.084 ;
    END
  END cfg_data[58]
  PIN cfg_data[59]
    DIRECTION INPUT ;
    USE SIGNAL ;
    PORT
      LAYER M5 ;
        RECT  13.44 0 13.464 0.084 ;
    END
  END cfg_data[59]
  PIN cfg_data[5]
    DIRECTION INPUT ;
    USE SIGNAL ;
    PORT
      LAYER M5 ;
        RECT  4.176 0 4.2 0.084 ;
    END
  END cfg_data[5]
  PIN cfg_data[60]
    DIRECTION INPUT ;
    USE SIGNAL ;
    PORT
      LAYER M5 ;
        RECT  13.632 0 13.656 0.084 ;
    END
  END cfg_data[60]
  PIN cfg_data[61]
    DIRECTION INPUT ;
    USE SIGNAL ;
    PORT
      LAYER M5 ;
        RECT  13.776 0 13.8 0.084 ;
    END
  END cfg_data[61]
  PIN cfg_data[62]
    DIRECTION INPUT ;
    USE SIGNAL ;
    PORT
      LAYER M5 ;
        RECT  13.968 0 13.992 0.084 ;
    END
  END cfg_data[62]
  PIN cfg_data[63]
    DIRECTION INPUT ;
    USE SIGNAL ;
    PORT
      LAYER M5 ;
        RECT  14.112 0 14.136 0.084 ;
    END
  END cfg_data[63]
  PIN cfg_data[64]
    DIRECTION INPUT ;
    USE SIGNAL ;
    PORT
      LAYER M5 ;
        RECT  14.304 0 14.328 0.084 ;
    END
  END cfg_data[64]
  PIN cfg_data[65]
    DIRECTION INPUT ;
    USE SIGNAL ;
    PORT
      LAYER M5 ;
        RECT  14.496 0 14.52 0.084 ;
    END
  END cfg_data[65]
  PIN cfg_data[66]
    DIRECTION INPUT ;
    USE SIGNAL ;
    PORT
      LAYER M5 ;
        RECT  14.64 0 14.664 0.084 ;
    END
  END cfg_data[66]
  PIN cfg_data[67]
    DIRECTION INPUT ;
    USE SIGNAL ;
    PORT
      LAYER M5 ;
        RECT  14.832 0 14.856 0.084 ;
    END
  END cfg_data[67]
  PIN cfg_data[68]
    DIRECTION INPUT ;
    USE SIGNAL ;
    PORT
      LAYER M5 ;
        RECT  14.976 0 15 0.084 ;
    END
  END cfg_data[68]
  PIN cfg_data[69]
    DIRECTION INPUT ;
    USE SIGNAL ;
    PORT
      LAYER M5 ;
        RECT  15.168 0 15.192 0.084 ;
    END
  END cfg_data[69]
  PIN cfg_data[6]
    DIRECTION INPUT ;
    USE SIGNAL ;
    PORT
      LAYER M5 ;
        RECT  4.32 0 4.344 0.084 ;
    END
  END cfg_data[6]
  PIN cfg_data[70]
    DIRECTION INPUT ;
    USE SIGNAL ;
    PORT
      LAYER M5 ;
        RECT  15.36 0 15.384 0.084 ;
    END
  END cfg_data[70]
  PIN cfg_data[71]
    DIRECTION INPUT ;
    USE SIGNAL ;
    PORT
      LAYER M5 ;
        RECT  15.504 0 15.528 0.084 ;
    END
  END cfg_data[71]
  PIN cfg_data[72]
    DIRECTION INPUT ;
    USE SIGNAL ;
    PORT
      LAYER M5 ;
        RECT  15.696 0 15.72 0.084 ;
    END
  END cfg_data[72]
  PIN cfg_data[73]
    DIRECTION INPUT ;
    USE SIGNAL ;
    PORT
      LAYER M5 ;
        RECT  15.84 0 15.864 0.084 ;
    END
  END cfg_data[73]
  PIN cfg_data[74]
    DIRECTION INPUT ;
    USE SIGNAL ;
    PORT
      LAYER M5 ;
        RECT  16.032 0 16.056 0.084 ;
    END
  END cfg_data[74]
  PIN cfg_data[75]
    DIRECTION INPUT ;
    USE SIGNAL ;
    PORT
      LAYER M5 ;
        RECT  16.176 0 16.2 0.084 ;
    END
  END cfg_data[75]
  PIN cfg_data[76]
    DIRECTION INPUT ;
    USE SIGNAL ;
    PORT
      LAYER M5 ;
        RECT  16.368 0 16.392 0.084 ;
    END
  END cfg_data[76]
  PIN cfg_data[77]
    DIRECTION INPUT ;
    USE SIGNAL ;
    PORT
      LAYER M5 ;
        RECT  16.56 0 16.584 0.084 ;
    END
  END cfg_data[77]
  PIN cfg_data[78]
    DIRECTION INPUT ;
    USE SIGNAL ;
    PORT
      LAYER M5 ;
        RECT  16.704 0 16.728 0.084 ;
    END
  END cfg_data[78]
  PIN cfg_data[79]
    DIRECTION INPUT ;
    USE SIGNAL ;
    PORT
      LAYER M5 ;
        RECT  16.896 0 16.92 0.084 ;
    END
  END cfg_data[79]
  PIN cfg_data[7]
    DIRECTION INPUT ;
    USE SIGNAL ;
    PORT
      LAYER M5 ;
        RECT  4.512 0 4.536 0.084 ;
    END
  END cfg_data[7]
  PIN cfg_data[80]
    DIRECTION INPUT ;
    USE SIGNAL ;
    PORT
      LAYER M5 ;
        RECT  17.04 0 17.064 0.084 ;
    END
  END cfg_data[80]
  PIN cfg_data[81]
    DIRECTION INPUT ;
    USE SIGNAL ;
    PORT
      LAYER M5 ;
        RECT  17.232 0 17.256 0.084 ;
    END
  END cfg_data[81]
  PIN cfg_data[82]
    DIRECTION INPUT ;
    USE SIGNAL ;
    PORT
      LAYER M5 ;
        RECT  17.424 0 17.448 0.084 ;
    END
  END cfg_data[82]
  PIN cfg_data[83]
    DIRECTION INPUT ;
    USE SIGNAL ;
    PORT
      LAYER M5 ;
        RECT  17.568 0 17.592 0.084 ;
    END
  END cfg_data[83]
  PIN cfg_data[84]
    DIRECTION INPUT ;
    USE SIGNAL ;
    PORT
      LAYER M5 ;
        RECT  17.76 0 17.784 0.084 ;
    END
  END cfg_data[84]
  PIN cfg_data[85]
    DIRECTION INPUT ;
    USE SIGNAL ;
    PORT
      LAYER M5 ;
        RECT  17.904 0 17.928 0.084 ;
    END
  END cfg_data[85]
  PIN cfg_data[86]
    DIRECTION INPUT ;
    USE SIGNAL ;
    PORT
      LAYER M5 ;
        RECT  18.096 0 18.12 0.084 ;
    END
  END cfg_data[86]
  PIN cfg_data[87]
    DIRECTION INPUT ;
    USE SIGNAL ;
    PORT
      LAYER M5 ;
        RECT  18.24 0 18.264 0.084 ;
    END
  END cfg_data[87]
  PIN cfg_data[88]
    DIRECTION INPUT ;
    USE SIGNAL ;
    PORT
      LAYER M5 ;
        RECT  18.432 0 18.456 0.084 ;
    END
  END cfg_data[88]
  PIN cfg_data[89]
    DIRECTION INPUT ;
    USE SIGNAL ;
    PORT
      LAYER M5 ;
        RECT  18.624 0 18.648 0.084 ;
    END
  END cfg_data[89]
  PIN cfg_data[8]
    DIRECTION INPUT ;
    USE SIGNAL ;
    PORT
      LAYER M5 ;
        RECT  4.704 0 4.728 0.084 ;
    END
  END cfg_data[8]
  PIN cfg_data[90]
    DIRECTION INPUT ;
    USE SIGNAL ;
    PORT
      LAYER M5 ;
        RECT  18.768 0 18.792 0.084 ;
    END
  END cfg_data[90]
  PIN cfg_data[91]
    DIRECTION INPUT ;
    USE SIGNAL ;
    PORT
      LAYER M5 ;
        RECT  18.96 0 18.984 0.084 ;
    END
  END cfg_data[91]
  PIN cfg_data[92]
    DIRECTION INPUT ;
    USE SIGNAL ;
    PORT
      LAYER M5 ;
        RECT  19.104 0 19.128 0.084 ;
    END
  END cfg_data[92]
  PIN cfg_data[93]
    DIRECTION INPUT ;
    USE SIGNAL ;
    PORT
      LAYER M5 ;
        RECT  19.296 0 19.32 0.084 ;
    END
  END cfg_data[93]
  PIN cfg_data[94]
    DIRECTION INPUT ;
    USE SIGNAL ;
    PORT
      LAYER M5 ;
        RECT  19.44 0 19.464 0.084 ;
    END
  END cfg_data[94]
  PIN cfg_data[95]
    DIRECTION INPUT ;
    USE SIGNAL ;
    PORT
      LAYER M5 ;
        RECT  19.632 0 19.656 0.084 ;
    END
  END cfg_data[95]
  PIN cfg_data[96]
    DIRECTION INPUT ;
    USE SIGNAL ;
    PORT
      LAYER M5 ;
        RECT  19.824 0 19.848 0.084 ;
    END
  END cfg_data[96]
  PIN cfg_data[97]
    DIRECTION INPUT ;
    USE SIGNAL ;
    PORT
      LAYER M5 ;
        RECT  19.968 0 19.992 0.084 ;
    END
  END cfg_data[97]
  PIN cfg_data[98]
    DIRECTION INPUT ;
    USE SIGNAL ;
    PORT
      LAYER M5 ;
        RECT  20.16 0 20.184 0.084 ;
    END
  END cfg_data[98]
  PIN cfg_data[99]
    DIRECTION INPUT ;
    USE SIGNAL ;
    PORT
      LAYER M5 ;
        RECT  20.304 0 20.328 0.084 ;
    END
  END cfg_data[99]
  PIN cfg_data[9]
    DIRECTION INPUT ;
    USE SIGNAL ;
    PORT
      LAYER M5 ;
        RECT  4.848 0 4.872 0.084 ;
    END
  END cfg_data[9]
  PIN cfg_target[0]
    DIRECTION INPUT ;
    USE SIGNAL ;
    PORT
      LAYER M5 ;
        RECT  47.328 0 47.352 0.084 ;
    END
  END cfg_target[0]
  PIN cfg_target[1]
    DIRECTION INPUT ;
    USE SIGNAL ;
    PORT
      LAYER M5 ;
        RECT  47.472 0 47.496 0.084 ;
    END
  END cfg_target[1]
  PIN cfg_target[2]
    DIRECTION INPUT ;
    USE SIGNAL ;
    PORT
      LAYER M5 ;
        RECT  47.664 0 47.688 0.084 ;
    END
  END cfg_target[2]
  PIN cfg_target[3]
    DIRECTION INPUT ;
    USE SIGNAL ;
    PORT
      LAYER M5 ;
        RECT  47.808 0 47.832 0.084 ;
    END
  END cfg_target[3]
  PIN cfg_target[4]
    DIRECTION INPUT ;
    USE SIGNAL ;
    PORT
      LAYER M5 ;
        RECT  48 0 48.024 0.084 ;
    END
  END cfg_target[4]
  PIN cfg_target[5]
    DIRECTION INPUT ;
    USE SIGNAL ;
    PORT
      LAYER M5 ;
        RECT  48.144 0 48.168 0.084 ;
    END
  END cfg_target[5]
  PIN cfg_target[6]
    DIRECTION INPUT ;
    USE SIGNAL ;
    PORT
      LAYER M5 ;
        RECT  48.336 0 48.36 0.084 ;
    END
  END cfg_target[6]
  PIN cfg_target[7]
    DIRECTION INPUT ;
    USE SIGNAL ;
    PORT
      LAYER M5 ;
        RECT  48.528 0 48.552 0.084 ;
    END
  END cfg_target[7]
  PIN cfg_v
    DIRECTION INPUT ;
    USE SIGNAL ;
    PORT
      LAYER M5 ;
        RECT  48.672 0 48.696 0.084 ;
    END
  END cfg_v
  PIN clk
    DIRECTION INPUT ;
    USE SIGNAL ;
    PORT
      LAYER M5 ;
        RECT  48.864 0 48.888 0.084 ;
    END
  END clk
  PIN clk_hbm
    DIRECTION INPUT ;
    USE SIGNAL ;
    PORT
      LAYER M5 ;
        RECT  1.2 51.756 1.224 51.84 ;
    END
  END clk_hbm
  PIN fault
    DIRECTION OUTPUT ;
    USE SIGNAL ;
    PORT
      LAYER M5 ;
        RECT  49.008 0 49.032 0.084 ;
    END
  END fault
  PIN pc_rst_n
    DIRECTION OUTPUT ;
    USE SIGNAL ;
    PORT
      LAYER M5 ;
        RECT  1.536 51.756 1.56 51.84 ;
    END
  END pc_rst_n
  PIN ready
    DIRECTION OUTPUT ;
    USE SIGNAL ;
    PORT
      LAYER M5 ;
        RECT  49.2 0 49.224 0.084 ;
    END
  END ready
  PIN refresh_reload[0]
    DIRECTION OUTPUT ;
    USE SIGNAL ;
    PORT
      LAYER M5 ;
        RECT  1.92 51.756 1.944 51.84 ;
    END
  END refresh_reload[0]
  PIN refresh_reload[100]
    DIRECTION OUTPUT ;
    USE SIGNAL ;
    PORT
      LAYER M5 ;
        RECT  39.984 51.756 40.008 51.84 ;
    END
  END refresh_reload[100]
  PIN refresh_reload[101]
    DIRECTION OUTPUT ;
    USE SIGNAL ;
    PORT
      LAYER M5 ;
        RECT  40.368 51.756 40.392 51.84 ;
    END
  END refresh_reload[101]
  PIN refresh_reload[102]
    DIRECTION OUTPUT ;
    USE SIGNAL ;
    PORT
      LAYER M5 ;
        RECT  40.752 51.756 40.776 51.84 ;
    END
  END refresh_reload[102]
  PIN refresh_reload[103]
    DIRECTION OUTPUT ;
    USE SIGNAL ;
    PORT
      LAYER M5 ;
        RECT  41.136 51.756 41.16 51.84 ;
    END
  END refresh_reload[103]
  PIN refresh_reload[104]
    DIRECTION OUTPUT ;
    USE SIGNAL ;
    PORT
      LAYER M5 ;
        RECT  41.52 51.756 41.544 51.84 ;
    END
  END refresh_reload[104]
  PIN refresh_reload[105]
    DIRECTION OUTPUT ;
    USE SIGNAL ;
    PORT
      LAYER M5 ;
        RECT  41.904 51.756 41.928 51.84 ;
    END
  END refresh_reload[105]
  PIN refresh_reload[106]
    DIRECTION OUTPUT ;
    USE SIGNAL ;
    PORT
      LAYER M5 ;
        RECT  42.288 51.756 42.312 51.84 ;
    END
  END refresh_reload[106]
  PIN refresh_reload[107]
    DIRECTION OUTPUT ;
    USE SIGNAL ;
    PORT
      LAYER M5 ;
        RECT  42.672 51.756 42.696 51.84 ;
    END
  END refresh_reload[107]
  PIN refresh_reload[108]
    DIRECTION OUTPUT ;
    USE SIGNAL ;
    PORT
      LAYER M5 ;
        RECT  43.008 51.756 43.032 51.84 ;
    END
  END refresh_reload[108]
  PIN refresh_reload[109]
    DIRECTION OUTPUT ;
    USE SIGNAL ;
    PORT
      LAYER M5 ;
        RECT  43.392 51.756 43.416 51.84 ;
    END
  END refresh_reload[109]
  PIN refresh_reload[10]
    DIRECTION OUTPUT ;
    USE SIGNAL ;
    PORT
      LAYER M5 ;
        RECT  5.76 51.756 5.784 51.84 ;
    END
  END refresh_reload[10]
  PIN refresh_reload[110]
    DIRECTION OUTPUT ;
    USE SIGNAL ;
    PORT
      LAYER M5 ;
        RECT  43.776 51.756 43.8 51.84 ;
    END
  END refresh_reload[110]
  PIN refresh_reload[111]
    DIRECTION OUTPUT ;
    USE SIGNAL ;
    PORT
      LAYER M5 ;
        RECT  44.16 51.756 44.184 51.84 ;
    END
  END refresh_reload[111]
  PIN refresh_reload[112]
    DIRECTION OUTPUT ;
    USE SIGNAL ;
    PORT
      LAYER M5 ;
        RECT  44.544 51.756 44.568 51.84 ;
    END
  END refresh_reload[112]
  PIN refresh_reload[113]
    DIRECTION OUTPUT ;
    USE SIGNAL ;
    PORT
      LAYER M5 ;
        RECT  44.928 51.756 44.952 51.84 ;
    END
  END refresh_reload[113]
  PIN refresh_reload[114]
    DIRECTION OUTPUT ;
    USE SIGNAL ;
    PORT
      LAYER M5 ;
        RECT  45.312 51.756 45.336 51.84 ;
    END
  END refresh_reload[114]
  PIN refresh_reload[115]
    DIRECTION OUTPUT ;
    USE SIGNAL ;
    PORT
      LAYER M5 ;
        RECT  45.696 51.756 45.72 51.84 ;
    END
  END refresh_reload[115]
  PIN refresh_reload[116]
    DIRECTION OUTPUT ;
    USE SIGNAL ;
    PORT
      LAYER M5 ;
        RECT  46.08 51.756 46.104 51.84 ;
    END
  END refresh_reload[116]
  PIN refresh_reload[117]
    DIRECTION OUTPUT ;
    USE SIGNAL ;
    PORT
      LAYER M5 ;
        RECT  46.464 51.756 46.488 51.84 ;
    END
  END refresh_reload[117]
  PIN refresh_reload[118]
    DIRECTION OUTPUT ;
    USE SIGNAL ;
    PORT
      LAYER M5 ;
        RECT  46.848 51.756 46.872 51.84 ;
    END
  END refresh_reload[118]
  PIN refresh_reload[119]
    DIRECTION OUTPUT ;
    USE SIGNAL ;
    PORT
      LAYER M5 ;
        RECT  47.232 51.756 47.256 51.84 ;
    END
  END refresh_reload[119]
  PIN refresh_reload[11]
    DIRECTION OUTPUT ;
    USE SIGNAL ;
    PORT
      LAYER M5 ;
        RECT  6.144 51.756 6.168 51.84 ;
    END
  END refresh_reload[11]
  PIN refresh_reload[120]
    DIRECTION OUTPUT ;
    USE SIGNAL ;
    PORT
      LAYER M5 ;
        RECT  47.616 51.756 47.64 51.84 ;
    END
  END refresh_reload[120]
  PIN refresh_reload[121]
    DIRECTION OUTPUT ;
    USE SIGNAL ;
    PORT
      LAYER M5 ;
        RECT  47.952 51.756 47.976 51.84 ;
    END
  END refresh_reload[121]
  PIN refresh_reload[122]
    DIRECTION OUTPUT ;
    USE SIGNAL ;
    PORT
      LAYER M5 ;
        RECT  48.336 51.756 48.36 51.84 ;
    END
  END refresh_reload[122]
  PIN refresh_reload[123]
    DIRECTION OUTPUT ;
    USE SIGNAL ;
    PORT
      LAYER M5 ;
        RECT  48.72 51.756 48.744 51.84 ;
    END
  END refresh_reload[123]
  PIN refresh_reload[124]
    DIRECTION OUTPUT ;
    USE SIGNAL ;
    PORT
      LAYER M5 ;
        RECT  49.104 51.756 49.128 51.84 ;
    END
  END refresh_reload[124]
  PIN refresh_reload[125]
    DIRECTION OUTPUT ;
    USE SIGNAL ;
    PORT
      LAYER M5 ;
        RECT  49.488 51.756 49.512 51.84 ;
    END
  END refresh_reload[125]
  PIN refresh_reload[126]
    DIRECTION OUTPUT ;
    USE SIGNAL ;
    PORT
      LAYER M5 ;
        RECT  49.872 51.756 49.896 51.84 ;
    END
  END refresh_reload[126]
  PIN refresh_reload[127]
    DIRECTION OUTPUT ;
    USE SIGNAL ;
    PORT
      LAYER M5 ;
        RECT  50.256 51.756 50.28 51.84 ;
    END
  END refresh_reload[127]
  PIN refresh_reload[12]
    DIRECTION OUTPUT ;
    USE SIGNAL ;
    PORT
      LAYER M5 ;
        RECT  6.528 51.756 6.552 51.84 ;
    END
  END refresh_reload[12]
  PIN refresh_reload[13]
    DIRECTION OUTPUT ;
    USE SIGNAL ;
    PORT
      LAYER M5 ;
        RECT  6.864 51.756 6.888 51.84 ;
    END
  END refresh_reload[13]
  PIN refresh_reload[14]
    DIRECTION OUTPUT ;
    USE SIGNAL ;
    PORT
      LAYER M5 ;
        RECT  7.248 51.756 7.272 51.84 ;
    END
  END refresh_reload[14]
  PIN refresh_reload[15]
    DIRECTION OUTPUT ;
    USE SIGNAL ;
    PORT
      LAYER M5 ;
        RECT  7.632 51.756 7.656 51.84 ;
    END
  END refresh_reload[15]
  PIN refresh_reload[16]
    DIRECTION OUTPUT ;
    USE SIGNAL ;
    PORT
      LAYER M5 ;
        RECT  8.016 51.756 8.04 51.84 ;
    END
  END refresh_reload[16]
  PIN refresh_reload[17]
    DIRECTION OUTPUT ;
    USE SIGNAL ;
    PORT
      LAYER M5 ;
        RECT  8.4 51.756 8.424 51.84 ;
    END
  END refresh_reload[17]
  PIN refresh_reload[18]
    DIRECTION OUTPUT ;
    USE SIGNAL ;
    PORT
      LAYER M5 ;
        RECT  8.784 51.756 8.808 51.84 ;
    END
  END refresh_reload[18]
  PIN refresh_reload[19]
    DIRECTION OUTPUT ;
    USE SIGNAL ;
    PORT
      LAYER M5 ;
        RECT  9.168 51.756 9.192 51.84 ;
    END
  END refresh_reload[19]
  PIN refresh_reload[1]
    DIRECTION OUTPUT ;
    USE SIGNAL ;
    PORT
      LAYER M5 ;
        RECT  2.304 51.756 2.328 51.84 ;
    END
  END refresh_reload[1]
  PIN refresh_reload[20]
    DIRECTION OUTPUT ;
    USE SIGNAL ;
    PORT
      LAYER M5 ;
        RECT  9.552 51.756 9.576 51.84 ;
    END
  END refresh_reload[20]
  PIN refresh_reload[21]
    DIRECTION OUTPUT ;
    USE SIGNAL ;
    PORT
      LAYER M5 ;
        RECT  9.936 51.756 9.96 51.84 ;
    END
  END refresh_reload[21]
  PIN refresh_reload[22]
    DIRECTION OUTPUT ;
    USE SIGNAL ;
    PORT
      LAYER M5 ;
        RECT  10.32 51.756 10.344 51.84 ;
    END
  END refresh_reload[22]
  PIN refresh_reload[23]
    DIRECTION OUTPUT ;
    USE SIGNAL ;
    PORT
      LAYER M5 ;
        RECT  10.704 51.756 10.728 51.84 ;
    END
  END refresh_reload[23]
  PIN refresh_reload[24]
    DIRECTION OUTPUT ;
    USE SIGNAL ;
    PORT
      LAYER M5 ;
        RECT  11.088 51.756 11.112 51.84 ;
    END
  END refresh_reload[24]
  PIN refresh_reload[25]
    DIRECTION OUTPUT ;
    USE SIGNAL ;
    PORT
      LAYER M5 ;
        RECT  11.472 51.756 11.496 51.84 ;
    END
  END refresh_reload[25]
  PIN refresh_reload[26]
    DIRECTION OUTPUT ;
    USE SIGNAL ;
    PORT
      LAYER M5 ;
        RECT  11.808 51.756 11.832 51.84 ;
    END
  END refresh_reload[26]
  PIN refresh_reload[27]
    DIRECTION OUTPUT ;
    USE SIGNAL ;
    PORT
      LAYER M5 ;
        RECT  12.192 51.756 12.216 51.84 ;
    END
  END refresh_reload[27]
  PIN refresh_reload[28]
    DIRECTION OUTPUT ;
    USE SIGNAL ;
    PORT
      LAYER M5 ;
        RECT  12.576 51.756 12.6 51.84 ;
    END
  END refresh_reload[28]
  PIN refresh_reload[29]
    DIRECTION OUTPUT ;
    USE SIGNAL ;
    PORT
      LAYER M5 ;
        RECT  12.96 51.756 12.984 51.84 ;
    END
  END refresh_reload[29]
  PIN refresh_reload[2]
    DIRECTION OUTPUT ;
    USE SIGNAL ;
    PORT
      LAYER M5 ;
        RECT  2.688 51.756 2.712 51.84 ;
    END
  END refresh_reload[2]
  PIN refresh_reload[30]
    DIRECTION OUTPUT ;
    USE SIGNAL ;
    PORT
      LAYER M5 ;
        RECT  13.344 51.756 13.368 51.84 ;
    END
  END refresh_reload[30]
  PIN refresh_reload[31]
    DIRECTION OUTPUT ;
    USE SIGNAL ;
    PORT
      LAYER M5 ;
        RECT  13.728 51.756 13.752 51.84 ;
    END
  END refresh_reload[31]
  PIN refresh_reload[32]
    DIRECTION OUTPUT ;
    USE SIGNAL ;
    PORT
      LAYER M5 ;
        RECT  14.112 51.756 14.136 51.84 ;
    END
  END refresh_reload[32]
  PIN refresh_reload[33]
    DIRECTION OUTPUT ;
    USE SIGNAL ;
    PORT
      LAYER M5 ;
        RECT  14.496 51.756 14.52 51.84 ;
    END
  END refresh_reload[33]
  PIN refresh_reload[34]
    DIRECTION OUTPUT ;
    USE SIGNAL ;
    PORT
      LAYER M5 ;
        RECT  14.88 51.756 14.904 51.84 ;
    END
  END refresh_reload[34]
  PIN refresh_reload[35]
    DIRECTION OUTPUT ;
    USE SIGNAL ;
    PORT
      LAYER M5 ;
        RECT  15.264 51.756 15.288 51.84 ;
    END
  END refresh_reload[35]
  PIN refresh_reload[36]
    DIRECTION OUTPUT ;
    USE SIGNAL ;
    PORT
      LAYER M5 ;
        RECT  15.648 51.756 15.672 51.84 ;
    END
  END refresh_reload[36]
  PIN refresh_reload[37]
    DIRECTION OUTPUT ;
    USE SIGNAL ;
    PORT
      LAYER M5 ;
        RECT  16.032 51.756 16.056 51.84 ;
    END
  END refresh_reload[37]
  PIN refresh_reload[38]
    DIRECTION OUTPUT ;
    USE SIGNAL ;
    PORT
      LAYER M5 ;
        RECT  16.416 51.756 16.44 51.84 ;
    END
  END refresh_reload[38]
  PIN refresh_reload[39]
    DIRECTION OUTPUT ;
    USE SIGNAL ;
    PORT
      LAYER M5 ;
        RECT  16.8 51.756 16.824 51.84 ;
    END
  END refresh_reload[39]
  PIN refresh_reload[3]
    DIRECTION OUTPUT ;
    USE SIGNAL ;
    PORT
      LAYER M5 ;
        RECT  3.072 51.756 3.096 51.84 ;
    END
  END refresh_reload[3]
  PIN refresh_reload[40]
    DIRECTION OUTPUT ;
    USE SIGNAL ;
    PORT
      LAYER M5 ;
        RECT  17.136 51.756 17.16 51.84 ;
    END
  END refresh_reload[40]
  PIN refresh_reload[41]
    DIRECTION OUTPUT ;
    USE SIGNAL ;
    PORT
      LAYER M5 ;
        RECT  17.52 51.756 17.544 51.84 ;
    END
  END refresh_reload[41]
  PIN refresh_reload[42]
    DIRECTION OUTPUT ;
    USE SIGNAL ;
    PORT
      LAYER M5 ;
        RECT  17.904 51.756 17.928 51.84 ;
    END
  END refresh_reload[42]
  PIN refresh_reload[43]
    DIRECTION OUTPUT ;
    USE SIGNAL ;
    PORT
      LAYER M5 ;
        RECT  18.288 51.756 18.312 51.84 ;
    END
  END refresh_reload[43]
  PIN refresh_reload[44]
    DIRECTION OUTPUT ;
    USE SIGNAL ;
    PORT
      LAYER M5 ;
        RECT  18.672 51.756 18.696 51.84 ;
    END
  END refresh_reload[44]
  PIN refresh_reload[45]
    DIRECTION OUTPUT ;
    USE SIGNAL ;
    PORT
      LAYER M5 ;
        RECT  19.056 51.756 19.08 51.84 ;
    END
  END refresh_reload[45]
  PIN refresh_reload[46]
    DIRECTION OUTPUT ;
    USE SIGNAL ;
    PORT
      LAYER M5 ;
        RECT  19.44 51.756 19.464 51.84 ;
    END
  END refresh_reload[46]
  PIN refresh_reload[47]
    DIRECTION OUTPUT ;
    USE SIGNAL ;
    PORT
      LAYER M5 ;
        RECT  19.824 51.756 19.848 51.84 ;
    END
  END refresh_reload[47]
  PIN refresh_reload[48]
    DIRECTION OUTPUT ;
    USE SIGNAL ;
    PORT
      LAYER M5 ;
        RECT  20.208 51.756 20.232 51.84 ;
    END
  END refresh_reload[48]
  PIN refresh_reload[49]
    DIRECTION OUTPUT ;
    USE SIGNAL ;
    PORT
      LAYER M5 ;
        RECT  20.592 51.756 20.616 51.84 ;
    END
  END refresh_reload[49]
  PIN refresh_reload[4]
    DIRECTION OUTPUT ;
    USE SIGNAL ;
    PORT
      LAYER M5 ;
        RECT  3.456 51.756 3.48 51.84 ;
    END
  END refresh_reload[4]
  PIN refresh_reload[50]
    DIRECTION OUTPUT ;
    USE SIGNAL ;
    PORT
      LAYER M5 ;
        RECT  20.976 51.756 21 51.84 ;
    END
  END refresh_reload[50]
  PIN refresh_reload[51]
    DIRECTION OUTPUT ;
    USE SIGNAL ;
    PORT
      LAYER M5 ;
        RECT  21.36 51.756 21.384 51.84 ;
    END
  END refresh_reload[51]
  PIN refresh_reload[52]
    DIRECTION OUTPUT ;
    USE SIGNAL ;
    PORT
      LAYER M5 ;
        RECT  21.744 51.756 21.768 51.84 ;
    END
  END refresh_reload[52]
  PIN refresh_reload[53]
    DIRECTION OUTPUT ;
    USE SIGNAL ;
    PORT
      LAYER M5 ;
        RECT  22.08 51.756 22.104 51.84 ;
    END
  END refresh_reload[53]
  PIN refresh_reload[54]
    DIRECTION OUTPUT ;
    USE SIGNAL ;
    PORT
      LAYER M5 ;
        RECT  22.464 51.756 22.488 51.84 ;
    END
  END refresh_reload[54]
  PIN refresh_reload[55]
    DIRECTION OUTPUT ;
    USE SIGNAL ;
    PORT
      LAYER M5 ;
        RECT  22.848 51.756 22.872 51.84 ;
    END
  END refresh_reload[55]
  PIN refresh_reload[56]
    DIRECTION OUTPUT ;
    USE SIGNAL ;
    PORT
      LAYER M5 ;
        RECT  23.232 51.756 23.256 51.84 ;
    END
  END refresh_reload[56]
  PIN refresh_reload[57]
    DIRECTION OUTPUT ;
    USE SIGNAL ;
    PORT
      LAYER M5 ;
        RECT  23.616 51.756 23.64 51.84 ;
    END
  END refresh_reload[57]
  PIN refresh_reload[58]
    DIRECTION OUTPUT ;
    USE SIGNAL ;
    PORT
      LAYER M5 ;
        RECT  24 51.756 24.024 51.84 ;
    END
  END refresh_reload[58]
  PIN refresh_reload[59]
    DIRECTION OUTPUT ;
    USE SIGNAL ;
    PORT
      LAYER M5 ;
        RECT  24.384 51.756 24.408 51.84 ;
    END
  END refresh_reload[59]
  PIN refresh_reload[5]
    DIRECTION OUTPUT ;
    USE SIGNAL ;
    PORT
      LAYER M5 ;
        RECT  3.84 51.756 3.864 51.84 ;
    END
  END refresh_reload[5]
  PIN refresh_reload[60]
    DIRECTION OUTPUT ;
    USE SIGNAL ;
    PORT
      LAYER M5 ;
        RECT  24.768 51.756 24.792 51.84 ;
    END
  END refresh_reload[60]
  PIN refresh_reload[61]
    DIRECTION OUTPUT ;
    USE SIGNAL ;
    PORT
      LAYER M5 ;
        RECT  25.152 51.756 25.176 51.84 ;
    END
  END refresh_reload[61]
  PIN refresh_reload[62]
    DIRECTION OUTPUT ;
    USE SIGNAL ;
    PORT
      LAYER M5 ;
        RECT  25.536 51.756 25.56 51.84 ;
    END
  END refresh_reload[62]
  PIN refresh_reload[63]
    DIRECTION OUTPUT ;
    USE SIGNAL ;
    PORT
      LAYER M5 ;
        RECT  25.92 51.756 25.944 51.84 ;
    END
  END refresh_reload[63]
  PIN refresh_reload[64]
    DIRECTION OUTPUT ;
    USE SIGNAL ;
    PORT
      LAYER M5 ;
        RECT  26.304 51.756 26.328 51.84 ;
    END
  END refresh_reload[64]
  PIN refresh_reload[65]
    DIRECTION OUTPUT ;
    USE SIGNAL ;
    PORT
      LAYER M5 ;
        RECT  26.688 51.756 26.712 51.84 ;
    END
  END refresh_reload[65]
  PIN refresh_reload[66]
    DIRECTION OUTPUT ;
    USE SIGNAL ;
    PORT
      LAYER M5 ;
        RECT  27.072 51.756 27.096 51.84 ;
    END
  END refresh_reload[66]
  PIN refresh_reload[67]
    DIRECTION OUTPUT ;
    USE SIGNAL ;
    PORT
      LAYER M5 ;
        RECT  27.408 51.756 27.432 51.84 ;
    END
  END refresh_reload[67]
  PIN refresh_reload[68]
    DIRECTION OUTPUT ;
    USE SIGNAL ;
    PORT
      LAYER M5 ;
        RECT  27.792 51.756 27.816 51.84 ;
    END
  END refresh_reload[68]
  PIN refresh_reload[69]
    DIRECTION OUTPUT ;
    USE SIGNAL ;
    PORT
      LAYER M5 ;
        RECT  28.176 51.756 28.2 51.84 ;
    END
  END refresh_reload[69]
  PIN refresh_reload[6]
    DIRECTION OUTPUT ;
    USE SIGNAL ;
    PORT
      LAYER M5 ;
        RECT  4.224 51.756 4.248 51.84 ;
    END
  END refresh_reload[6]
  PIN refresh_reload[70]
    DIRECTION OUTPUT ;
    USE SIGNAL ;
    PORT
      LAYER M5 ;
        RECT  28.56 51.756 28.584 51.84 ;
    END
  END refresh_reload[70]
  PIN refresh_reload[71]
    DIRECTION OUTPUT ;
    USE SIGNAL ;
    PORT
      LAYER M5 ;
        RECT  28.944 51.756 28.968 51.84 ;
    END
  END refresh_reload[71]
  PIN refresh_reload[72]
    DIRECTION OUTPUT ;
    USE SIGNAL ;
    PORT
      LAYER M5 ;
        RECT  29.328 51.756 29.352 51.84 ;
    END
  END refresh_reload[72]
  PIN refresh_reload[73]
    DIRECTION OUTPUT ;
    USE SIGNAL ;
    PORT
      LAYER M5 ;
        RECT  29.712 51.756 29.736 51.84 ;
    END
  END refresh_reload[73]
  PIN refresh_reload[74]
    DIRECTION OUTPUT ;
    USE SIGNAL ;
    PORT
      LAYER M5 ;
        RECT  30.096 51.756 30.12 51.84 ;
    END
  END refresh_reload[74]
  PIN refresh_reload[75]
    DIRECTION OUTPUT ;
    USE SIGNAL ;
    PORT
      LAYER M5 ;
        RECT  30.48 51.756 30.504 51.84 ;
    END
  END refresh_reload[75]
  PIN refresh_reload[76]
    DIRECTION OUTPUT ;
    USE SIGNAL ;
    PORT
      LAYER M5 ;
        RECT  30.864 51.756 30.888 51.84 ;
    END
  END refresh_reload[76]
  PIN refresh_reload[77]
    DIRECTION OUTPUT ;
    USE SIGNAL ;
    PORT
      LAYER M5 ;
        RECT  31.248 51.756 31.272 51.84 ;
    END
  END refresh_reload[77]
  PIN refresh_reload[78]
    DIRECTION OUTPUT ;
    USE SIGNAL ;
    PORT
      LAYER M5 ;
        RECT  31.632 51.756 31.656 51.84 ;
    END
  END refresh_reload[78]
  PIN refresh_reload[79]
    DIRECTION OUTPUT ;
    USE SIGNAL ;
    PORT
      LAYER M5 ;
        RECT  32.016 51.756 32.04 51.84 ;
    END
  END refresh_reload[79]
  PIN refresh_reload[7]
    DIRECTION OUTPUT ;
    USE SIGNAL ;
    PORT
      LAYER M5 ;
        RECT  4.608 51.756 4.632 51.84 ;
    END
  END refresh_reload[7]
  PIN refresh_reload[80]
    DIRECTION OUTPUT ;
    USE SIGNAL ;
    PORT
      LAYER M5 ;
        RECT  32.4 51.756 32.424 51.84 ;
    END
  END refresh_reload[80]
  PIN refresh_reload[81]
    DIRECTION OUTPUT ;
    USE SIGNAL ;
    PORT
      LAYER M5 ;
        RECT  32.736 51.756 32.76 51.84 ;
    END
  END refresh_reload[81]
  PIN refresh_reload[82]
    DIRECTION OUTPUT ;
    USE SIGNAL ;
    PORT
      LAYER M5 ;
        RECT  33.12 51.756 33.144 51.84 ;
    END
  END refresh_reload[82]
  PIN refresh_reload[83]
    DIRECTION OUTPUT ;
    USE SIGNAL ;
    PORT
      LAYER M5 ;
        RECT  33.504 51.756 33.528 51.84 ;
    END
  END refresh_reload[83]
  PIN refresh_reload[84]
    DIRECTION OUTPUT ;
    USE SIGNAL ;
    PORT
      LAYER M5 ;
        RECT  33.888 51.756 33.912 51.84 ;
    END
  END refresh_reload[84]
  PIN refresh_reload[85]
    DIRECTION OUTPUT ;
    USE SIGNAL ;
    PORT
      LAYER M5 ;
        RECT  34.272 51.756 34.296 51.84 ;
    END
  END refresh_reload[85]
  PIN refresh_reload[86]
    DIRECTION OUTPUT ;
    USE SIGNAL ;
    PORT
      LAYER M5 ;
        RECT  34.656 51.756 34.68 51.84 ;
    END
  END refresh_reload[86]
  PIN refresh_reload[87]
    DIRECTION OUTPUT ;
    USE SIGNAL ;
    PORT
      LAYER M5 ;
        RECT  35.04 51.756 35.064 51.84 ;
    END
  END refresh_reload[87]
  PIN refresh_reload[88]
    DIRECTION OUTPUT ;
    USE SIGNAL ;
    PORT
      LAYER M5 ;
        RECT  35.424 51.756 35.448 51.84 ;
    END
  END refresh_reload[88]
  PIN refresh_reload[89]
    DIRECTION OUTPUT ;
    USE SIGNAL ;
    PORT
      LAYER M5 ;
        RECT  35.808 51.756 35.832 51.84 ;
    END
  END refresh_reload[89]
  PIN refresh_reload[8]
    DIRECTION OUTPUT ;
    USE SIGNAL ;
    PORT
      LAYER M5 ;
        RECT  4.992 51.756 5.016 51.84 ;
    END
  END refresh_reload[8]
  PIN refresh_reload[90]
    DIRECTION OUTPUT ;
    USE SIGNAL ;
    PORT
      LAYER M5 ;
        RECT  36.192 51.756 36.216 51.84 ;
    END
  END refresh_reload[90]
  PIN refresh_reload[91]
    DIRECTION OUTPUT ;
    USE SIGNAL ;
    PORT
      LAYER M5 ;
        RECT  36.576 51.756 36.6 51.84 ;
    END
  END refresh_reload[91]
  PIN refresh_reload[92]
    DIRECTION OUTPUT ;
    USE SIGNAL ;
    PORT
      LAYER M5 ;
        RECT  36.96 51.756 36.984 51.84 ;
    END
  END refresh_reload[92]
  PIN refresh_reload[93]
    DIRECTION OUTPUT ;
    USE SIGNAL ;
    PORT
      LAYER M5 ;
        RECT  37.344 51.756 37.368 51.84 ;
    END
  END refresh_reload[93]
  PIN refresh_reload[94]
    DIRECTION OUTPUT ;
    USE SIGNAL ;
    PORT
      LAYER M5 ;
        RECT  37.68 51.756 37.704 51.84 ;
    END
  END refresh_reload[94]
  PIN refresh_reload[95]
    DIRECTION OUTPUT ;
    USE SIGNAL ;
    PORT
      LAYER M5 ;
        RECT  38.064 51.756 38.088 51.84 ;
    END
  END refresh_reload[95]
  PIN refresh_reload[96]
    DIRECTION OUTPUT ;
    USE SIGNAL ;
    PORT
      LAYER M5 ;
        RECT  38.448 51.756 38.472 51.84 ;
    END
  END refresh_reload[96]
  PIN refresh_reload[97]
    DIRECTION OUTPUT ;
    USE SIGNAL ;
    PORT
      LAYER M5 ;
        RECT  38.832 51.756 38.856 51.84 ;
    END
  END refresh_reload[97]
  PIN refresh_reload[98]
    DIRECTION OUTPUT ;
    USE SIGNAL ;
    PORT
      LAYER M5 ;
        RECT  39.216 51.756 39.24 51.84 ;
    END
  END refresh_reload[98]
  PIN refresh_reload[99]
    DIRECTION OUTPUT ;
    USE SIGNAL ;
    PORT
      LAYER M5 ;
        RECT  39.6 51.756 39.624 51.84 ;
    END
  END refresh_reload[99]
  PIN refresh_reload[9]
    DIRECTION OUTPUT ;
    USE SIGNAL ;
    PORT
      LAYER M5 ;
        RECT  5.376 51.756 5.4 51.84 ;
    END
  END refresh_reload[9]
  PIN rst_hbm_n
    DIRECTION INPUT ;
    USE SIGNAL ;
    PORT
      LAYER M5 ;
        RECT  50.64 51.756 50.664 51.84 ;
    END
  END rst_hbm_n
  PIN rst_n
    DIRECTION INPUT ;
    USE SIGNAL ;
    PORT
      LAYER M5 ;
        RECT  49.344 0 49.368 0.084 ;
    END
  END rst_n
  PIN tgt[0]
    DIRECTION INPUT ;
    USE SIGNAL ;
    PORT
      LAYER M5 ;
        RECT  49.536 0 49.56 0.084 ;
    END
  END tgt[0]
  PIN tgt[1]
    DIRECTION INPUT ;
    USE SIGNAL ;
    PORT
      LAYER M5 ;
        RECT  49.728 0 49.752 0.084 ;
    END
  END tgt[1]
  PIN tgt[2]
    DIRECTION INPUT ;
    USE SIGNAL ;
    PORT
      LAYER M5 ;
        RECT  49.872 0 49.896 0.084 ;
    END
  END tgt[2]
  PIN tgt[3]
    DIRECTION INPUT ;
    USE SIGNAL ;
    PORT
      LAYER M5 ;
        RECT  50.064 0 50.088 0.084 ;
    END
  END tgt[3]
  PIN tgt[4]
    DIRECTION INPUT ;
    USE SIGNAL ;
    PORT
      LAYER M5 ;
        RECT  50.208 0 50.232 0.084 ;
    END
  END tgt[4]
  PIN tgt[5]
    DIRECTION INPUT ;
    USE SIGNAL ;
    PORT
      LAYER M5 ;
        RECT  50.4 0 50.424 0.084 ;
    END
  END tgt[5]
  PIN tgt[6]
    DIRECTION INPUT ;
    USE SIGNAL ;
    PORT
      LAYER M5 ;
        RECT  50.592 0 50.616 0.084 ;
    END
  END tgt[6]
  PIN tgt[7]
    DIRECTION INPUT ;
    USE SIGNAL ;
    PORT
      LAYER M5 ;
        RECT  50.736 0 50.76 0.084 ;
    END
  END tgt[7]
  PIN VDD
    DIRECTION INOUT ;
    USE POWER ;
    PORT
      LAYER M5 ;
        RECT  45.792 2.151 45.912 49.689 ;
        RECT  40.392 2.151 40.512 49.689 ;
        RECT  34.992 2.151 35.112 49.689 ;
        RECT  29.592 2.151 29.712 49.689 ;
        RECT  24.192 2.151 24.312 49.689 ;
        RECT  18.792 2.151 18.912 49.689 ;
        RECT  13.392 2.151 13.512 49.689 ;
        RECT  7.992 2.151 8.112 49.689 ;
        RECT  2.592 2.151 2.712 49.689 ;
    END
  END VDD
  PIN VSS
    DIRECTION INOUT ;
    USE GROUND ;
    PORT
      LAYER M5 ;
        RECT  45.6 2.137 45.72 49.703 ;
        RECT  40.2 2.137 40.32 49.703 ;
        RECT  34.8 2.137 34.92 49.703 ;
        RECT  29.4 2.137 29.52 49.703 ;
        RECT  24 2.137 24.12 49.703 ;
        RECT  18.6 2.137 18.72 49.703 ;
        RECT  13.2 2.137 13.32 49.703 ;
        RECT  7.8 2.137 7.92 49.703 ;
        RECT  2.4 2.137 2.52 49.703 ;
    END
  END VSS
  OBS
    LAYER RVTN ;
     RECT  2.16 2.16 49.68 2.295 ;
     RECT  2.16 2.565 49.68 2.835 ;
     RECT  2.16 3.105 49.68 3.375 ;
     RECT  2.16 3.645 49.68 3.915 ;
     RECT  2.16 4.185 49.68 4.455 ;
     RECT  2.16 4.725 49.68 4.995 ;
     RECT  2.16 5.265 49.68 5.535 ;
     RECT  2.16 5.805 49.68 6.075 ;
     RECT  2.16 6.345 49.68 6.615 ;
     RECT  2.16 6.885 49.68 7.155 ;
     RECT  2.16 7.425 49.68 7.695 ;
     RECT  2.16 7.965 49.68 8.235 ;
     RECT  2.16 8.505 49.68 8.775 ;
     RECT  2.16 9.045 49.68 9.315 ;
     RECT  2.16 9.585 49.68 9.855 ;
     RECT  2.16 10.125 49.68 10.395 ;
     RECT  2.16 10.665 49.68 10.935 ;
     RECT  2.16 11.205 49.68 11.475 ;
     RECT  2.16 11.745 49.68 12.015 ;
     RECT  2.16 12.285 49.68 12.555 ;
     RECT  2.16 12.825 49.68 13.095 ;
     RECT  2.16 13.365 49.68 13.635 ;
     RECT  2.16 13.905 49.68 14.175 ;
     RECT  2.16 14.445 49.68 14.715 ;
     RECT  2.16 14.985 49.68 15.255 ;
     RECT  2.16 15.525 49.68 15.795 ;
     RECT  2.16 16.065 49.68 16.335 ;
     RECT  2.16 16.605 49.68 16.875 ;
     RECT  2.16 17.145 49.68 17.415 ;
     RECT  2.16 17.685 49.68 17.955 ;
     RECT  2.16 18.225 49.68 18.495 ;
     RECT  2.16 18.765 49.68 19.035 ;
     RECT  2.16 19.305 49.68 19.575 ;
     RECT  2.16 19.845 49.68 20.115 ;
     RECT  2.16 20.385 49.68 20.655 ;
     RECT  2.16 20.925 49.68 21.195 ;
     RECT  2.16 21.465 49.68 21.735 ;
     RECT  2.16 22.005 49.68 22.275 ;
     RECT  2.16 22.545 49.68 22.815 ;
     RECT  2.16 23.085 49.68 23.355 ;
     RECT  2.16 23.625 49.68 23.895 ;
     RECT  2.16 24.165 49.68 24.435 ;
     RECT  2.16 24.705 49.68 24.975 ;
     RECT  2.16 25.245 49.68 25.515 ;
     RECT  2.16 25.785 49.68 26.055 ;
     RECT  2.16 26.325 49.68 26.595 ;
     RECT  2.16 26.865 49.68 27.135 ;
     RECT  2.16 27.405 49.68 27.675 ;
     RECT  2.16 27.945 49.68 28.215 ;
     RECT  2.16 28.485 49.68 28.755 ;
     RECT  2.16 29.025 49.68 29.295 ;
     RECT  2.16 29.565 49.68 29.835 ;
     RECT  2.16 30.105 49.68 30.375 ;
     RECT  2.16 30.645 49.68 30.915 ;
     RECT  2.16 31.185 49.68 31.455 ;
     RECT  2.16 31.725 49.68 31.995 ;
     RECT  2.16 32.265 49.68 32.535 ;
     RECT  2.16 32.805 49.68 33.075 ;
     RECT  2.16 33.345 49.68 33.615 ;
     RECT  2.16 33.885 49.68 34.155 ;
     RECT  2.16 34.425 49.68 34.695 ;
     RECT  2.16 34.965 49.68 35.235 ;
     RECT  2.16 35.505 49.68 35.775 ;
     RECT  2.16 36.045 49.68 36.315 ;
     RECT  2.16 36.585 49.68 36.855 ;
     RECT  2.16 37.125 49.68 37.395 ;
     RECT  2.16 37.665 49.68 37.935 ;
     RECT  2.16 38.205 49.68 38.475 ;
     RECT  2.16 38.745 49.68 39.015 ;
     RECT  2.16 39.285 49.68 39.555 ;
     RECT  2.16 39.825 49.68 40.095 ;
     RECT  2.16 40.365 49.68 40.635 ;
     RECT  2.16 40.905 49.68 41.175 ;
     RECT  2.16 41.445 49.68 41.715 ;
     RECT  2.16 41.985 49.68 42.255 ;
     RECT  2.16 42.525 49.68 42.795 ;
     RECT  2.16 43.065 49.68 43.335 ;
     RECT  2.16 43.605 49.68 43.875 ;
     RECT  2.16 44.145 49.68 44.415 ;
     RECT  2.16 44.685 49.68 44.955 ;
     RECT  2.16 45.225 49.68 45.495 ;
     RECT  2.16 45.765 49.68 46.035 ;
     RECT  2.16 46.305 49.68 46.575 ;
     RECT  2.16 46.845 49.68 47.115 ;
     RECT  2.16 47.385 49.68 47.655 ;
     RECT  2.16 47.925 49.68 48.195 ;
     RECT  2.16 48.465 49.68 48.735 ;
     RECT  2.16 49.005 49.68 49.275 ;
     RECT  2.16 49.545 49.68 49.68 ;
    LAYER RVTP ;
     RECT  2.16 2.295 49.68 2.565 ;
     RECT  2.16 2.835 49.68 3.105 ;
     RECT  2.16 3.375 49.68 3.645 ;
     RECT  2.16 3.915 49.68 4.185 ;
     RECT  2.16 4.455 49.68 4.725 ;
     RECT  2.16 4.995 49.68 5.265 ;
     RECT  2.16 5.535 49.68 5.805 ;
     RECT  2.16 6.075 49.68 6.345 ;
     RECT  2.16 6.615 49.68 6.885 ;
     RECT  2.16 7.155 49.68 7.425 ;
     RECT  2.16 7.695 49.68 7.965 ;
     RECT  2.16 8.235 49.68 8.505 ;
     RECT  2.16 8.775 49.68 9.045 ;
     RECT  2.16 9.315 49.68 9.585 ;
     RECT  2.16 9.855 49.68 10.125 ;
     RECT  2.16 10.395 49.68 10.665 ;
     RECT  2.16 10.935 49.68 11.205 ;
     RECT  2.16 11.475 49.68 11.745 ;
     RECT  2.16 12.015 49.68 12.285 ;
     RECT  2.16 12.555 49.68 12.825 ;
     RECT  2.16 13.095 49.68 13.365 ;
     RECT  2.16 13.635 49.68 13.905 ;
     RECT  2.16 14.175 49.68 14.445 ;
     RECT  2.16 14.715 49.68 14.985 ;
     RECT  2.16 15.255 49.68 15.525 ;
     RECT  2.16 15.795 49.68 16.065 ;
     RECT  2.16 16.335 49.68 16.605 ;
     RECT  2.16 16.875 49.68 17.145 ;
     RECT  2.16 17.415 49.68 17.685 ;
     RECT  2.16 17.955 49.68 18.225 ;
     RECT  2.16 18.495 49.68 18.765 ;
     RECT  2.16 19.035 49.68 19.305 ;
     RECT  2.16 19.575 49.68 19.845 ;
     RECT  2.16 20.115 49.68 20.385 ;
     RECT  2.16 20.655 49.68 20.925 ;
     RECT  2.16 21.195 49.68 21.465 ;
     RECT  2.16 21.735 49.68 22.005 ;
     RECT  2.16 22.275 49.68 22.545 ;
     RECT  2.16 22.815 49.68 23.085 ;
     RECT  2.16 23.355 49.68 23.625 ;
     RECT  2.16 23.895 49.68 24.165 ;
     RECT  2.16 24.435 49.68 24.705 ;
     RECT  2.16 24.975 49.68 25.245 ;
     RECT  2.16 25.515 49.68 25.785 ;
     RECT  2.16 26.055 49.68 26.325 ;
     RECT  2.16 26.595 49.68 26.865 ;
     RECT  2.16 27.135 49.68 27.405 ;
     RECT  2.16 27.675 49.68 27.945 ;
     RECT  2.16 28.215 49.68 28.485 ;
     RECT  2.16 28.755 49.68 29.025 ;
     RECT  2.16 29.295 49.68 29.565 ;
     RECT  2.16 29.835 49.68 30.105 ;
     RECT  2.16 30.375 49.68 30.645 ;
     RECT  2.16 30.915 49.68 31.185 ;
     RECT  2.16 31.455 49.68 31.725 ;
     RECT  2.16 31.995 49.68 32.265 ;
     RECT  2.16 32.535 49.68 32.805 ;
     RECT  2.16 33.075 49.68 33.345 ;
     RECT  2.16 33.615 49.68 33.885 ;
     RECT  2.16 34.155 49.68 34.425 ;
     RECT  2.16 34.695 49.68 34.965 ;
     RECT  2.16 35.235 49.68 35.505 ;
     RECT  2.16 35.775 49.68 36.045 ;
     RECT  2.16 36.315 49.68 36.585 ;
     RECT  2.16 36.855 49.68 37.125 ;
     RECT  2.16 37.395 49.68 37.665 ;
     RECT  2.16 37.935 49.68 38.205 ;
     RECT  2.16 38.475 49.68 38.745 ;
     RECT  2.16 39.015 49.68 39.285 ;
     RECT  2.16 39.555 49.68 39.825 ;
     RECT  2.16 40.095 49.68 40.365 ;
     RECT  2.16 40.635 49.68 40.905 ;
     RECT  2.16 41.175 49.68 41.445 ;
     RECT  2.16 41.715 49.68 41.985 ;
     RECT  2.16 42.255 49.68 42.525 ;
     RECT  2.16 42.795 49.68 43.065 ;
     RECT  2.16 43.335 49.68 43.605 ;
     RECT  2.16 43.875 49.68 44.145 ;
     RECT  2.16 44.415 49.68 44.685 ;
     RECT  2.16 44.955 49.68 45.225 ;
     RECT  2.16 45.495 49.68 45.765 ;
     RECT  2.16 46.035 49.68 46.305 ;
     RECT  2.16 46.575 49.68 46.845 ;
     RECT  2.16 47.115 49.68 47.385 ;
     RECT  2.16 47.655 49.68 47.925 ;
     RECT  2.16 48.195 49.68 48.465 ;
     RECT  2.16 48.735 49.68 49.005 ;
     RECT  2.16 49.275 49.68 49.545 ;
    LAYER M1 ;
     RECT  2.16 2.151 49.68 49.689 ;
    LAYER M2 ;
     RECT  1.075 2.106 1.795 2.124 ;
     RECT  1.795 2.106 2.16 2.592 ;
     RECT  2.119 5.202 2.16 5.22 ;
     RECT  2.16 2.106 3.911 49.689 ;
     RECT  3.911 2.151 22.675 49.689 ;
     RECT  22.675 2.151 41.207 49.734 ;
     RECT  41.207 2.151 46.147 49.689 ;
     RECT  46.147 2.106 46.939 49.689 ;
     RECT  46.939 2.034 48.335 49.689 ;
     RECT  48.335 2.106 48.695 49.689 ;
     RECT  48.695 2.151 49.68 49.689 ;
     RECT  49.68 3.042 49.739 3.06 ;
     RECT  49.68 3.852 49.883 4.374 ;
     RECT  49.68 46.044 49.883 46.062 ;
     RECT  49.68 5.814 50.099 5.832 ;
     RECT  49.883 4.356 50.207 4.374 ;
    LAYER M3 ;
     RECT  48.96 0.523 48.978 0.571 ;
     RECT  47.988 0.571 48.978 0.619 ;
     RECT  50.076 0.091 50.094 1.675 ;
     RECT  7.956 0.091 7.974 1.723 ;
     RECT  22.212 0.091 22.23 1.723 ;
     RECT  2.736 1.723 24.354 1.771 ;
     RECT  25.128 1.723 25.146 1.771 ;
     RECT  2.736 1.771 25.146 1.819 ;
     RECT  47.34 0.619 48.978 2.029 ;
     RECT  1.08 1.723 1.962 2.129 ;
     RECT  1.8 2.129 1.962 2.143 ;
     RECT  2.736 1.819 25.182 2.143 ;
     RECT  34.2 0.043 34.218 2.143 ;
     RECT  46.152 2.101 46.17 2.143 ;
     RECT  46.944 2.029 48.978 2.251 ;
     RECT  49.716 1.675 50.094 2.251 ;
     RECT  1.8 2.143 25.182 2.263 ;
     RECT  45.615 2.143 46.17 2.335 ;
     RECT  46.944 2.251 50.202 2.335 ;
     RECT  29.415 2.143 29.505 2.413 ;
     RECT  34.2 2.143 34.905 2.413 ;
     RECT  40.215 2.143 40.305 2.413 ;
     RECT  1.8 2.263 25.362 2.597 ;
     RECT  45.615 2.335 50.202 2.605 ;
     RECT  45.432 2.605 50.202 2.827 ;
     RECT  44.136 2.803 44.154 2.861 ;
     RECT  45.18 2.827 50.202 2.875 ;
     RECT  45.036 2.875 50.202 3.029 ;
     RECT  2.376 2.597 25.362 3.181 ;
     RECT  2.376 3.181 25.686 3.271 ;
     RECT  2.376 3.271 26.406 3.451 ;
     RECT  45.18 3.029 50.202 3.605 ;
     RECT  2.376 3.451 26.442 3.979 ;
     RECT  45.615 3.605 50.202 4.379 ;
     RECT  45.615 4.379 50.094 4.559 ;
     RECT  2.124 3.979 26.442 4.955 ;
     RECT  47.196 4.559 50.094 5.117 ;
     RECT  2.124 4.955 13.95 5.225 ;
     RECT  47.304 5.117 50.094 5.603 ;
     RECT  10.872 5.225 13.95 5.701 ;
     RECT  14.724 4.955 26.442 5.701 ;
     RECT  10.872 5.701 26.442 5.729 ;
     RECT  2.304 5.225 10.026 5.765 ;
     RECT  47.772 5.603 50.094 5.837 ;
     RECT  47.772 5.837 49.518 5.885 ;
     RECT  47.88 5.885 49.518 6.071 ;
     RECT  47.88 6.071 49.302 6.269 ;
     RECT  34.2 2.413 35.097 28.949 ;
     RECT  32.4 4.891 32.418 29.029 ;
     RECT  32.4 29.029 33.066 29.219 ;
     RECT  32.4 29.219 32.418 29.371 ;
     RECT  32.328 29.371 32.418 29.489 ;
     RECT  32.328 29.489 32.346 29.605 ;
     RECT  31.932 29.605 32.346 30.605 ;
     RECT  12.42 5.729 26.442 36.121 ;
     RECT  12.42 36.121 27.09 36.461 ;
     RECT  10.872 5.729 11.394 42.799 ;
     RECT  2.415 5.765 10.026 42.899 ;
     RECT  10.836 42.799 11.394 42.989 ;
     RECT  12.42 36.461 26.442 43.141 ;
     RECT  12.42 43.141 27.09 43.439 ;
     RECT  12.564 43.439 27.09 43.529 ;
     RECT  47.88 6.269 48.15 43.565 ;
     RECT  31.392 43.411 31.41 43.609 ;
     RECT  30.78 43.609 31.41 43.645 ;
     RECT  32.328 30.605 32.346 43.645 ;
     RECT  4.176 42.899 10.026 43.915 ;
     RECT  10.872 42.989 11.394 43.915 ;
     RECT  30.78 43.645 32.346 43.979 ;
     RECT  12.6 43.529 27.09 44.041 ;
     RECT  31.428 43.979 32.346 44.069 ;
     RECT  32.04 44.069 32.346 44.141 ;
     RECT  12.6 44.041 27.45 44.149 ;
     RECT  12.6 44.149 27.63 44.299 ;
     RECT  40.215 2.413 40.497 44.395 ;
     RECT  32.04 44.141 32.31 44.411 ;
     RECT  2.415 42.899 3.402 44.419 ;
     RECT  4.176 43.915 11.394 44.419 ;
     RECT  12.6 44.299 27.702 44.429 ;
     RECT  12.6 44.429 27.594 44.447 ;
     RECT  2.34 44.419 11.394 44.477 ;
     RECT  2.415 44.477 11.394 44.491 ;
     RECT  44.784 44.221 44.802 44.491 ;
     RECT  45.615 4.559 45.897 44.491 ;
     RECT  2.415 44.491 11.79 44.539 ;
     RECT  12.6 44.447 27.558 44.539 ;
     RECT  34.815 28.949 35.097 44.689 ;
     RECT  37.224 44.635 37.242 44.761 ;
     RECT  32.292 44.411 32.31 44.887 ;
     RECT  47.304 44.347 47.322 44.923 ;
     RECT  29.415 2.413 29.697 45.031 ;
     RECT  47.268 44.923 47.322 45.031 ;
     RECT  48.132 43.565 48.15 45.031 ;
     RECT  29.052 45.031 29.697 45.163 ;
     RECT  30.816 44.971 30.834 45.163 ;
     RECT  2.415 44.539 27.558 45.193 ;
     RECT  39.348 44.959 39.366 45.229 ;
     RECT  40.215 44.395 41.058 45.229 ;
     RECT  29.052 45.163 30.834 45.257 ;
     RECT  2.415 45.193 27.666 45.293 ;
     RECT  34.452 44.689 35.097 45.427 ;
     RECT  47.268 45.031 48.15 45.427 ;
     RECT  39.348 45.229 41.058 45.455 ;
     RECT  44.784 44.491 45.897 45.463 ;
     RECT  39.348 45.455 40.497 45.491 ;
     RECT  34.452 45.427 35.586 45.535 ;
     RECT  47.232 45.427 48.15 45.661 ;
     RECT  36.504 44.761 37.242 45.841 ;
     RECT  38.088 44.419 38.106 45.841 ;
     RECT  47.232 45.661 48.402 45.841 ;
     RECT  49.14 45.697 49.158 45.841 ;
     RECT  36.504 45.841 38.106 46.039 ;
     RECT  47.232 45.841 49.338 46.039 ;
     RECT  2.415 45.293 27.558 46.066 ;
     RECT  47.232 46.039 49.878 46.157 ;
     RECT  29.415 45.257 30.834 46.201 ;
     RECT  42.768 44.995 42.786 46.201 ;
     RECT  43.56 45.931 43.578 46.201 ;
     RECT  39.636 45.491 40.497 46.219 ;
     RECT  28.908 46.201 30.834 46.237 ;
     RECT  36.504 46.039 38.322 46.237 ;
     RECT  39.42 46.219 40.497 46.237 ;
     RECT  32.292 44.887 32.526 46.264 ;
     RECT  28.8 46.237 30.834 46.267 ;
     RECT  32.04 46.264 32.526 46.267 ;
     RECT  34.164 45.535 35.586 46.309 ;
     RECT  36.504 46.237 40.497 46.309 ;
     RECT  47.232 46.157 49.446 46.345 ;
     RECT  33.336 46.315 33.354 46.381 ;
     RECT  34.164 46.309 40.497 46.381 ;
     RECT  42.768 46.201 43.578 46.381 ;
     RECT  44.352 45.463 45.897 46.381 ;
     RECT  46.656 46.345 49.446 46.381 ;
     RECT  28.764 46.267 30.834 46.471 ;
     RECT  31.932 46.267 32.526 46.471 ;
     RECT  28.764 46.471 32.526 46.507 ;
     RECT  33.264 46.381 33.354 46.507 ;
     RECT  28.764 46.507 33.354 46.555 ;
     RECT  28.692 46.555 33.354 46.579 ;
     RECT  34.164 46.381 40.59 46.579 ;
     RECT  41.364 46.471 41.382 46.579 ;
     RECT  28.692 46.579 40.59 46.603 ;
     RECT  41.364 46.579 42.03 46.603 ;
     RECT  2.415 46.066 27.594 46.747 ;
     RECT  28.692 46.603 42.03 46.777 ;
     RECT  2.34 46.747 27.594 46.795 ;
     RECT  28.332 46.777 42.03 46.795 ;
     RECT  2.34 46.795 42.03 46.849 ;
     RECT  42.768 46.381 49.446 46.849 ;
     RECT  2.34 46.849 49.446 47.011 ;
     RECT  2.304 47.011 49.446 47.191 ;
     RECT  2.304 47.191 49.482 47.579 ;
     RECT  2.34 47.579 49.482 48.235 ;
     RECT  2.34 48.235 49.554 48.361 ;
     RECT  2.268 48.361 49.554 49.037 ;
     RECT  2.34 49.037 49.554 49.325 ;
     RECT  2.34 49.325 37.17 49.343 ;
     RECT  2.34 49.343 29.697 49.427 ;
     RECT  30.42 49.343 37.17 49.505 ;
     RECT  37.908 49.325 49.554 49.505 ;
     RECT  2.34 49.427 29.574 49.517 ;
     RECT  4.212 49.517 29.574 49.541 ;
     RECT  30.528 49.505 37.026 49.541 ;
     RECT  41.976 49.505 43.506 49.541 ;
     RECT  2.34 49.517 3.402 49.577 ;
     RECT  4.428 49.541 29.574 49.577 ;
     RECT  30.528 49.541 30.87 49.577 ;
     RECT  31.644 49.541 37.026 49.577 ;
     RECT  7.632 49.577 26.442 49.613 ;
     RECT  31.644 49.577 35.838 49.613 ;
     RECT  7.632 49.613 20.25 49.697 ;
     RECT  21.528 49.613 26.442 49.739 ;
     RECT  2.34 49.577 3.186 49.805 ;
     RECT  27.288 49.577 29.574 49.901 ;
     RECT  21.528 49.739 22.194 50.141 ;
     RECT  31.644 49.613 31.662 50.141 ;
     RECT  2.34 49.805 2.754 50.189 ;
     RECT  4.428 49.577 6.894 50.189 ;
     RECT  7.632 49.697 12.582 50.189 ;
     RECT  13.464 49.697 20.25 50.189 ;
     RECT  21.888 50.141 22.194 50.189 ;
     RECT  23.004 49.739 26.442 50.189 ;
     RECT  27.396 49.901 29.574 50.189 ;
     RECT  30.636 49.577 30.87 50.189 ;
     RECT  32.436 49.613 35.838 50.189 ;
     RECT  36.684 49.577 36.702 50.189 ;
     RECT  38.088 49.505 41.238 50.189 ;
     RECT  44.244 49.505 49.554 50.189 ;
     RECT  5.076 50.189 5.778 50.429 ;
     RECT  2.736 50.189 2.754 50.717 ;
     RECT  5.76 50.429 5.778 50.717 ;
     RECT  6.876 50.189 6.894 50.717 ;
     RECT  7.632 50.189 8.046 50.717 ;
     RECT  8.784 50.189 9.594 50.717 ;
     RECT  10.332 50.189 12.582 50.717 ;
     RECT  13.788 50.189 17.55 50.717 ;
     RECT  18.288 50.189 18.306 50.717 ;
     RECT  19.044 50.189 20.25 50.717 ;
     RECT  22.176 50.189 22.194 50.717 ;
     RECT  23.616 50.189 23.634 50.717 ;
     RECT  24.444 50.189 24.462 50.717 ;
     RECT  25.2 50.189 25.974 50.717 ;
     RECT  27.396 50.189 27.81 50.717 ;
     RECT  28.944 50.189 29.358 50.717 ;
     RECT  30.852 50.189 30.87 50.717 ;
     RECT  32.436 50.189 32.886 50.717 ;
     RECT  33.948 50.189 35.838 50.717 ;
     RECT  38.088 50.189 38.106 50.717 ;
     RECT  38.844 50.189 39.258 50.717 ;
     RECT  40.032 50.189 40.77 50.717 ;
     RECT  41.976 49.541 43.398 50.717 ;
     RECT  44.964 50.189 45.306 50.717 ;
     RECT  46.08 50.189 49.554 50.717 ;
     RECT  9.108 50.717 9.126 50.765 ;
     RECT  40.752 50.717 40.77 50.765 ;
     RECT  45.288 50.717 45.306 50.765 ;
    LAYER M4 ;
     RECT  1.237 4.56 1.429 4.584 ;
     RECT  1.429 4.56 1.573 4.68 ;
     RECT  1.573 4.56 2.069 5.016 ;
     RECT  1.189 47.136 2.293 47.16 ;
     RECT  1.525 50.16 2.293 50.184 ;
     RECT  1.025 1.728 2.408 1.752 ;
     RECT  2.069 3.984 2.408 5.016 ;
     RECT  2.293 44.448 2.408 45.24 ;
     RECT  2.293 46.752 2.408 47.16 ;
     RECT  1.909 49.008 2.408 49.032 ;
     RECT  2.293 50.16 2.408 50.712 ;
     RECT  2.408 1.728 2.704 50.712 ;
     RECT  2.704 47.136 2.765 48.504 ;
     RECT  2.704 49.488 2.765 50.712 ;
     RECT  2.704 3.984 2.837 4.008 ;
     RECT  2.704 45.12 2.867 46.056 ;
     RECT  2.765 47.28 2.867 48.504 ;
     RECT  2.867 45.12 3.125 45.144 ;
     RECT  2.867 47.28 3.125 48.456 ;
     RECT  2.765 49.488 3.197 49.8 ;
     RECT  3.125 47.904 3.737 48.456 ;
     RECT  2.704 5.664 3.805 5.688 ;
     RECT  3.197 49.488 3.829 49.56 ;
     RECT  2.704 1.728 3.913 2.904 ;
     RECT  3.913 1.728 3.917 3.144 ;
     RECT  3.829 49.104 3.989 49.56 ;
     RECT  3.805 5.088 4.241 5.688 ;
     RECT  3.737 47.904 4.273 47.928 ;
     RECT  3.917 2.88 4.525 3.144 ;
     RECT  4.273 47.28 4.741 47.928 ;
     RECT  4.741 47.28 4.777 48.408 ;
     RECT  4.213 49.584 4.96 50.184 ;
     RECT  4.96 49.536 5.065 50.184 ;
     RECT  5.065 49.536 5.141 50.424 ;
     RECT  4.777 46.8 5.209 48.408 ;
     RECT  5.209 46.8 5.245 48.504 ;
     RECT  3.917 1.728 5.641 1.8 ;
     RECT  4.525 2.88 5.641 3.432 ;
     RECT  5.641 1.728 5.747 3.432 ;
     RECT  5.141 50.16 5.749 50.424 ;
     RECT  5.747 2.88 5.753 3.432 ;
     RECT  5.029 4.56 5.785 4.584 ;
     RECT  4.241 5.664 5.785 5.688 ;
     RECT  5.785 4.56 5.789 5.688 ;
     RECT  5.789 5.184 5.825 5.688 ;
     RECT  5.749 50.16 5.833 50.712 ;
     RECT  5.245 46.608 6.181 48.504 ;
     RECT  6.181 46.608 6.185 48.792 ;
     RECT  5.753 2.88 6.689 3.336 ;
     RECT  5.747 1.728 6.757 1.8 ;
     RECT  5.833 50.16 6.853 50.424 ;
     RECT  6.185 47.568 7.237 48.792 ;
     RECT  6.853 50.16 7.237 50.712 ;
     RECT  6.757 1.728 7.808 2.28 ;
     RECT  6.689 3.312 7.808 3.336 ;
     RECT  5.825 5.184 7.808 5.208 ;
     RECT  7.237 47.568 7.808 50.712 ;
     RECT  7.945 0.096 8.029 0.12 ;
     RECT  7.808 1.728 8.104 50.712 ;
     RECT  8.104 50.16 8.525 50.712 ;
     RECT  8.104 46.704 8.921 48.744 ;
     RECT  8.921 47.568 9.029 48.744 ;
     RECT  8.104 1.728 9.065 1.848 ;
     RECT  8.525 50.4 9.097 50.712 ;
     RECT  9.097 50.4 9.203 50.76 ;
     RECT  8.104 44.688 9.709 44.712 ;
     RECT  8.104 4.56 9.749 5.208 ;
     RECT  9.203 50.4 9.884 50.712 ;
     RECT  9.884 50.16 9.971 50.712 ;
     RECT  9.065 1.728 10.165 1.8 ;
     RECT  9.709 44.688 10.181 45.144 ;
     RECT  10.181 44.688 10.249 45.048 ;
     RECT  10.165 1.728 10.253 1.848 ;
     RECT  10.249 44.544 10.289 45.048 ;
     RECT  9.029 47.568 10.393 48.456 ;
     RECT  9.749 5.136 10.685 5.208 ;
     RECT  10.289 44.544 10.825 45 ;
     RECT  10.825 44.496 11.801 45 ;
     RECT  10.253 1.728 11.893 1.8 ;
     RECT  10.393 46.8 11.905 48.456 ;
     RECT  11.893 1.728 11.981 1.896 ;
     RECT  11.801 44.544 12.089 45 ;
     RECT  11.077 3.408 12.373 3.432 ;
     RECT  11.905 46.608 12.517 48.456 ;
     RECT  9.971 50.4 12.637 50.712 ;
     RECT  12.517 46.608 12.877 48.984 ;
     RECT  12.877 46.512 12.949 48.984 ;
     RECT  12.637 50.4 12.949 50.424 ;
     RECT  11.981 1.728 13.093 1.8 ;
     RECT  12.373 3.408 13.201 4.008 ;
     RECT  13.093 1.728 13.208 2.28 ;
     RECT  13.201 3.408 13.208 4.152 ;
     RECT  10.685 5.184 13.208 5.208 ;
     RECT  12.089 44.784 13.208 45 ;
     RECT  12.949 46.512 13.208 50.424 ;
     RECT  13.208 1.728 13.493 50.424 ;
     RECT  13.493 1.728 13.504 49.422 ;
     RECT  13.493 50.4 13.717 50.424 ;
     RECT  13.504 44.16 13.889 44.184 ;
     RECT  13.504 4.128 14.321 4.152 ;
     RECT  13.504 45.696 14.321 49.032 ;
     RECT  14.321 45.984 14.485 49.032 ;
     RECT  13.717 50.4 14.485 50.712 ;
     RECT  14.485 45.984 14.609 50.712 ;
     RECT  13.504 5.184 14.713 5.208 ;
     RECT  14.821 43.008 15.001 43.032 ;
     RECT  15.001 42.816 15.073 43.032 ;
     RECT  13.504 1.728 15.145 1.8 ;
     RECT  15.073 42.768 15.185 43.032 ;
     RECT  14.609 45.984 15.299 49.032 ;
     RECT  15.299 45.984 15.329 48.408 ;
     RECT  15.185 42.816 15.473 43.032 ;
     RECT  15.329 45.984 15.577 48.168 ;
     RECT  14.609 50.4 15.637 50.712 ;
     RECT  15.001 44.496 15.685 44.52 ;
     RECT  14.713 2.832 15.721 2.856 ;
     RECT  14.713 4.224 15.721 5.208 ;
     RECT  15.721 2.832 15.725 5.208 ;
     RECT  15.685 44.4 15.761 44.52 ;
     RECT  15.577 45.6 15.761 48.168 ;
     RECT  15.637 49.584 15.761 50.712 ;
     RECT  15.725 2.832 15.869 3.336 ;
     RECT  15.761 44.4 15.869 44.424 ;
     RECT  15.145 1.728 15.901 1.848 ;
     RECT  15.761 45.6 15.901 47.928 ;
     RECT  15.901 1.728 16.067 2.28 ;
     RECT  15.901 45.408 16.121 47.928 ;
     RECT  15.901 43.056 16.225 43.08 ;
     RECT  15.869 3.264 16.301 3.336 ;
     RECT  16.301 3.312 16.445 3.336 ;
     RECT  16.121 47.904 16.729 47.928 ;
     RECT  16.729 47.904 16.945 48.264 ;
     RECT  16.121 45.408 17.125 46.872 ;
     RECT  16.945 47.904 17.125 48.792 ;
     RECT  16.225 43.056 17.237 44.376 ;
     RECT  17.125 45.408 17.237 48.792 ;
     RECT  17.237 43.056 17.341 43.32 ;
     RECT  17.341 42.864 17.413 43.32 ;
     RECT  17.237 47.904 17.665 48.792 ;
     RECT  15.761 50.4 17.893 50.712 ;
     RECT  17.237 45.408 17.953 46.92 ;
     RECT  17.665 47.904 18.061 48.84 ;
     RECT  16.067 1.728 18.421 1.848 ;
     RECT  18.421 1.728 18.608 2.28 ;
     RECT  15.725 5.184 18.608 5.208 ;
     RECT  17.413 42.816 18.608 43.32 ;
     RECT  17.953 44.496 18.608 46.92 ;
     RECT  18.061 47.904 18.608 48.984 ;
     RECT  17.893 50.16 18.608 50.712 ;
     RECT  18.608 1.728 18.785 50.712 ;
     RECT  18.785 1.728 18.904 49.422 ;
     RECT  18.904 42.96 19.397 48.984 ;
     RECT  19.397 44.928 19.469 48.984 ;
     RECT  19.469 46.512 19.541 48.984 ;
     RECT  18.904 4.08 19.793 4.104 ;
     RECT  18.904 1.728 19.969 1.848 ;
     RECT  19.969 1.728 20.195 2.28 ;
     RECT  18.785 50.4 20.261 50.712 ;
     RECT  19.397 42.96 20.437 43.944 ;
     RECT  19.469 44.928 20.437 45.288 ;
     RECT  19.541 46.512 20.581 48.936 ;
     RECT  20.261 50.4 20.581 50.424 ;
     RECT  20.437 42.96 20.981 45.288 ;
     RECT  20.581 46.512 21.011 50.424 ;
     RECT  21.011 46.512 21.125 48.936 ;
     RECT  20.981 44.64 21.229 45.288 ;
     RECT  21.229 44.64 21.373 45.384 ;
     RECT  21.373 44.64 22.057 45.816 ;
     RECT  21.011 50.112 22.069 50.424 ;
     RECT  22.057 44.448 22.165 45.816 ;
     RECT  21.125 46.848 22.165 48.936 ;
     RECT  22.069 50.112 22.205 50.712 ;
     RECT  18.904 5.184 22.273 5.208 ;
     RECT  22.201 0.096 22.285 0.12 ;
     RECT  22.165 44.448 22.345 48.936 ;
     RECT  22.205 50.112 22.345 50.424 ;
     RECT  22.345 44.448 22.499 50.424 ;
     RECT  22.417 17.904 22.7 17.928 ;
     RECT  20.195 1.728 22.733 1.8 ;
     RECT  22.273 4.512 22.787 5.208 ;
     RECT  22.7 17.664 22.787 17.928 ;
     RECT  22.499 44.448 22.849 48.84 ;
     RECT  20.981 42.96 23.065 42.984 ;
     RECT  22.849 44.4 23.065 48.84 ;
     RECT  22.417 3.312 23.317 3.336 ;
     RECT  22.787 4.512 23.317 5.112 ;
     RECT  22.733 1.728 23.461 1.848 ;
     RECT  22.499 50.112 23.605 50.424 ;
     RECT  23.461 1.728 24.008 2.28 ;
     RECT  23.317 3.312 24.008 5.112 ;
     RECT  22.787 17.904 24.008 17.928 ;
     RECT  23.065 42.96 24.008 48.84 ;
     RECT  23.605 50.112 24.008 50.712 ;
     RECT  24.008 1.728 24.304 50.712 ;
     RECT  24.304 1.728 24.323 2.04 ;
     RECT  24.304 4.512 24.545 4.536 ;
     RECT  24.304 50.16 24.869 50.712 ;
     RECT  24.323 1.728 25.157 1.848 ;
     RECT  25.157 1.824 25.193 1.848 ;
     RECT  24.304 43.248 25.333 45.24 ;
     RECT  24.304 46.224 25.333 49.032 ;
     RECT  25.333 43.248 25.337 49.032 ;
     RECT  24.304 25.776 25.909 25.8 ;
     RECT  24.304 17.904 25.955 17.928 ;
     RECT  25.909 25.776 25.957 25.944 ;
     RECT  24.869 50.4 25.985 50.712 ;
     RECT  25.945 35.952 26.029 35.976 ;
     RECT  25.337 43.488 26.129 49.032 ;
     RECT  25.985 50.4 26.293 50.424 ;
     RECT  26.129 43.536 26.309 49.032 ;
     RECT  25.957 25.776 26.345 26.04 ;
     RECT  26.309 43.968 26.777 49.032 ;
     RECT  26.777 44.16 26.885 49.032 ;
     RECT  26.885 44.304 27.061 49.032 ;
     RECT  26.293 50.16 27.061 50.424 ;
     RECT  27.061 36.432 27.145 36.456 ;
     RECT  27.061 44.304 27.317 50.424 ;
     RECT  27.317 50.16 27.385 50.424 ;
     RECT  27.317 44.304 27.443 49.032 ;
     RECT  27.443 44.304 27.569 48.936 ;
     RECT  27.569 44.304 27.677 45.288 ;
     RECT  27.677 44.304 27.713 45.192 ;
     RECT  27.385 50.16 27.865 50.712 ;
     RECT  27.569 46.512 28.753 48.936 ;
     RECT  27.865 50.16 28.933 50.424 ;
     RECT  28.753 46.272 29.041 48.936 ;
     RECT  28.933 50.16 29.369 50.712 ;
     RECT  24.304 3.312 29.408 3.336 ;
     RECT  26.345 25.776 29.408 25.8 ;
     RECT  27.713 44.352 29.408 45.192 ;
     RECT  29.041 46.272 29.408 49.032 ;
     RECT  29.369 50.16 29.408 50.424 ;
     RECT  29.408 2.148 29.512 50.424 ;
     RECT  29.512 2.418 29.704 50.424 ;
     RECT  29.704 44.352 30.233 45.192 ;
     RECT  29.704 50.16 30.841 50.424 ;
     RECT  30.233 44.352 30.845 45 ;
     RECT  30.841 50.16 30.925 50.712 ;
     RECT  30.845 44.352 31.057 44.664 ;
     RECT  29.704 46.32 31.237 49.032 ;
     RECT  30.925 50.16 31.237 50.424 ;
     RECT  31.057 43.872 31.715 44.664 ;
     RECT  31.237 46.32 31.921 50.424 ;
     RECT  31.921 46.272 32.069 50.424 ;
     RECT  32.069 46.32 32.177 50.424 ;
     RECT  32.177 50.4 32.381 50.424 ;
     RECT  32.381 50.4 32.897 50.712 ;
     RECT  32.177 46.32 33.365 48.792 ;
     RECT  32.897 50.4 33.452 50.424 ;
     RECT  33.452 50.16 33.539 50.424 ;
     RECT  33.365 46.608 33.829 48.792 ;
     RECT  33.539 50.4 33.877 50.424 ;
     RECT  29.704 3.312 34.808 3.336 ;
     RECT  29.704 25.776 34.808 25.8 ;
     RECT  31.715 44.352 34.808 44.664 ;
     RECT  33.829 46.608 34.808 49.224 ;
     RECT  33.877 50.4 34.808 50.712 ;
     RECT  34.808 2.148 34.912 50.712 ;
     RECT  34.912 2.418 35.104 49.422 ;
     RECT  35.104 46.512 35.273 48.792 ;
     RECT  34.912 50.4 35.849 50.712 ;
     RECT  35.273 46.512 36.277 48.744 ;
     RECT  35.849 50.4 36.565 50.424 ;
     RECT  36.277 46.512 36.949 48.888 ;
     RECT  36.565 50.16 36.949 50.424 ;
     RECT  36.949 46.512 37.037 50.424 ;
     RECT  37.037 46.512 37.213 49.32 ;
     RECT  35.104 44.352 37.253 44.664 ;
     RECT  37.213 46.368 37.573 49.32 ;
     RECT  37.573 46.32 37.613 49.32 ;
     RECT  37.613 46.32 37.717 48.936 ;
     RECT  37.037 50.4 38.033 50.424 ;
     RECT  38.033 50.4 38.396 50.712 ;
     RECT  38.396 50.16 38.483 50.712 ;
     RECT  37.717 46.224 38.945 48.936 ;
     RECT  38.483 50.4 39.589 50.712 ;
     RECT  35.104 3.312 40.208 3.336 ;
     RECT  35.104 25.776 40.208 25.8 ;
     RECT  37.253 44.352 40.208 44.424 ;
     RECT  38.945 46.224 40.208 48.792 ;
     RECT  39.589 50.16 40.208 50.712 ;
     RECT  40.208 2.148 40.312 50.712 ;
     RECT  40.312 2.418 40.504 50.712 ;
     RECT  40.504 46.608 40.673 48.984 ;
     RECT  40.504 50.16 40.7 50.712 ;
     RECT  40.7 50.16 40.787 50.76 ;
     RECT  40.504 44.352 41.069 44.424 ;
     RECT  40.787 50.16 41.249 50.424 ;
     RECT  40.673 46.848 41.509 48.984 ;
     RECT  41.509 46.848 41.609 49.32 ;
     RECT  41.609 46.848 41.749 48.984 ;
     RECT  41.749 46.512 41.825 48.984 ;
     RECT  41.249 50.4 41.893 50.424 ;
     RECT  41.893 50.4 43.453 50.712 ;
     RECT  41.825 46.512 43.765 48.84 ;
     RECT  43.765 46.512 43.852 49.032 ;
     RECT  40.504 3.312 44.125 3.336 ;
     RECT  43.453 50.4 44.149 50.424 ;
     RECT  43.852 46.512 44.453 48.792 ;
     RECT  44.149 50.16 44.909 50.424 ;
     RECT  44.909 50.16 45.26 50.712 ;
     RECT  45.26 50.16 45.347 50.76 ;
     RECT  44.125 2.832 45.608 3.336 ;
     RECT  40.504 25.776 45.608 25.8 ;
     RECT  41.069 44.352 45.608 44.376 ;
     RECT  44.453 46.512 45.608 48.408 ;
     RECT  45.347 50.16 45.608 50.712 ;
     RECT  45.608 2.148 45.712 50.712 ;
     RECT  45.712 2.418 45.893 50.712 ;
     RECT  45.893 2.418 45.904 49.422 ;
     RECT  45.904 46.512 46.433 48.504 ;
     RECT  45.904 2.592 46.505 3.336 ;
     RECT  46.433 46.512 46.829 46.872 ;
     RECT  47.113 4.368 47.185 4.392 ;
     RECT  34.189 0.048 47.329 0.072 ;
     RECT  45.904 44.352 47.333 44.376 ;
     RECT  46.505 2.832 47.369 3.336 ;
     RECT  47.329 0.048 47.437 0.648 ;
     RECT  47.317 1.728 47.437 1.752 ;
     RECT  47.185 4.368 47.441 5.112 ;
     RECT  46.433 47.856 47.509 48.504 ;
     RECT  47.437 0.048 47.521 1.752 ;
     RECT  47.441 4.368 47.585 4.392 ;
     RECT  47.521 1.728 47.612 1.752 ;
     RECT  47.369 2.832 47.612 2.856 ;
     RECT  47.509 47.76 47.873 48.504 ;
     RECT  46.829 46.512 47.909 46.536 ;
     RECT  47.612 1.728 47.981 2.856 ;
     RECT  45.893 50.4 48.325 50.712 ;
     RECT  47.873 47.856 48.337 48.504 ;
     RECT  47.981 1.728 48.377 2.28 ;
     RECT  47.761 5.856 48.521 5.88 ;
     RECT  48.445 3.984 48.563 4.008 ;
     RECT  48.337 47.856 48.773 48.84 ;
     RECT  48.773 47.856 48.881 48.36 ;
     RECT  45.904 25.776 48.899 25.8 ;
     RECT  48.881 48 49.097 48.36 ;
     RECT  47.521 0.048 49.139 0.648 ;
     RECT  49.097 48.336 49.169 48.36 ;
     RECT  48.325 50.112 49.345 50.712 ;
     RECT  49.345 49.584 49.523 50.712 ;
     RECT  48.377 1.776 49.676 2.28 ;
     RECT  49.676 1.68 49.763 2.28 ;
     RECT  49.849 46.128 49.933 46.152 ;
     RECT  49.139 0.096 50.105 0.648 ;
     RECT  49.157 3.408 50.243 3.432 ;
     RECT  49.523 50.4 50.291 50.712 ;
     RECT  50.105 0.528 50.435 0.648 ;
     RECT  49.763 2.256 50.627 2.28 ;
     RECT  50.291 50.4 50.675 50.424 ;
     RECT  50.435 0.528 50.771 0.552 ;
    LAYER M5 ;
     RECT  47.328 0.016 50.76 0.563 ;
     RECT  1.056 0.016 25.176 1.763 ;
     RECT  47.328 0.563 50.616 1.763 ;
     RECT  1.248 1.763 21.72 1.811 ;
     RECT  6.912 1.811 9 1.859 ;
     RECT  10.176 1.811 10.2 1.859 ;
     RECT  15.168 1.811 16.056 1.859 ;
     RECT  17.04 1.811 20.184 1.859 ;
     RECT  22.752 1.763 25.176 1.859 ;
     RECT  11.904 1.811 11.928 1.907 ;
     RECT  29.4 2.137 29.52 2.151 ;
     RECT  34.8 2.137 34.92 2.151 ;
     RECT  40.2 2.137 40.32 2.151 ;
     RECT  45.6 2.137 45.72 2.151 ;
     RECT  1.248 1.811 3.528 2.291 ;
     RECT  5.712 1.811 5.736 2.291 ;
     RECT  6.912 1.859 8.112 2.291 ;
     RECT  13.104 1.811 13.512 2.291 ;
     RECT  16.032 1.859 16.056 2.291 ;
     RECT  18.432 1.859 18.912 2.291 ;
     RECT  20.16 1.859 20.184 2.291 ;
     RECT  23.568 1.859 24.312 2.291 ;
     RECT  47.664 1.763 50.616 2.291 ;
     RECT  24 2.291 24.312 3.301 ;
     RECT  48.528 2.291 49.224 3.443 ;
     RECT  50.208 2.291 50.232 3.443 ;
     RECT  1.248 2.291 2.808 4.019 ;
     RECT  48.528 3.443 48.888 4.019 ;
     RECT  1.248 4.019 2.712 4.595 ;
     RECT  1.44 4.595 2.712 4.691 ;
     RECT  23.424 3.301 24.312 4.883 ;
     RECT  1.584 4.691 2.712 5.027 ;
     RECT  22.752 5.077 22.776 17.699 ;
     RECT  48.864 4.019 48.888 25.811 ;
     RECT  25.92 17.893 25.944 25.955 ;
     RECT  25.968 26.005 25.992 35.987 ;
     RECT  24 4.883 24.312 43.765 ;
     RECT  23.28 43.765 24.312 44.003 ;
     RECT  2.4 5.027 2.712 44.437 ;
     RECT  22.8 44.581 22.824 44.771 ;
     RECT  2.304 44.437 2.712 45.109 ;
     RECT  34.8 2.151 35.112 46.501 ;
     RECT  31.68 43.861 31.704 46.547 ;
     RECT  29.4 2.151 29.712 46.645 ;
     RECT  7.8 2.291 8.112 46.693 ;
     RECT  2.304 45.109 2.856 46.787 ;
     RECT  13.2 2.291 13.512 46.837 ;
     RECT  18.6 2.291 18.912 46.885 ;
     RECT  27.072 36.421 27.096 46.885 ;
     RECT  27.072 46.885 27.192 46.931 ;
     RECT  27.168 46.931 27.192 47.029 ;
     RECT  28.704 46.645 29.712 47.029 ;
     RECT  27.168 47.029 29.712 47.171 ;
     RECT  24 44.003 24.312 47.269 ;
     RECT  31.728 46.693 31.752 47.363 ;
     RECT  34.8 46.501 35.832 47.363 ;
     RECT  34.8 47.363 35.112 47.653 ;
     RECT  44.448 46.597 44.472 47.845 ;
     RECT  45.6 2.151 45.912 47.845 ;
     RECT  5.856 46.741 5.88 47.891 ;
     RECT  7.8 46.693 8.904 47.891 ;
     RECT  24 47.269 25.128 47.891 ;
     RECT  28.704 47.171 29.712 47.891 ;
     RECT  44.448 47.845 44.616 47.891 ;
     RECT  12.24 46.837 13.512 48.083 ;
     RECT  14.928 46.837 14.952 48.133 ;
     RECT  14.928 48.133 15.288 48.179 ;
     RECT  41.76 46.501 41.784 48.227 ;
     RECT  44.592 47.891 44.616 48.419 ;
     RECT  29.4 47.891 29.712 48.421 ;
     RECT  33.84 47.653 35.112 48.421 ;
     RECT  10.08 47.845 10.104 48.467 ;
     RECT  18 46.885 18.912 48.467 ;
     RECT  2.4 46.787 2.856 48.515 ;
     RECT  45.6 47.845 46.152 48.515 ;
     RECT  15.264 48.179 15.288 48.803 ;
     RECT  1.2 47.125 1.224 48.997 ;
     RECT  2.4 48.515 2.712 48.997 ;
     RECT  27.168 47.171 27.432 48.997 ;
     RECT  25.632 48.709 25.656 49.043 ;
     RECT  26.688 48.997 27.432 49.043 ;
     RECT  33.12 48.421 35.112 49.235 ;
     RECT  37.68 48.421 37.704 49.285 ;
     RECT  1.2 48.997 2.712 49.477 ;
     RECT  3.84 49.093 3.864 49.477 ;
     RECT  7.8 47.891 8.112 49.525 ;
     RECT  13.2 48.083 13.512 49.525 ;
     RECT  36.192 48.421 36.216 49.525 ;
     RECT  37.344 49.285 37.704 49.525 ;
     RECT  1.2 49.477 3.864 49.573 ;
     RECT  4.992 49.525 5.016 49.573 ;
     RECT  31.248 49.333 31.272 49.573 ;
     RECT  49.872 46.117 49.896 49.573 ;
     RECT  12.96 49.525 13.512 49.689 ;
     RECT  18.6 48.467 18.912 49.689 ;
     RECT  34.8 49.235 35.112 49.689 ;
     RECT  45.6 48.515 45.912 49.689 ;
     RECT  7.248 49.525 8.112 49.703 ;
     RECT  18.6 49.689 18.72 49.703 ;
     RECT  29.4 48.421 30.12 49.703 ;
     RECT  34.8 49.689 34.92 49.703 ;
     RECT  40.2 2.151 40.512 49.703 ;
     RECT  45.6 49.689 45.72 49.703 ;
     RECT  20.592 49.573 21 50.101 ;
     RECT  22.464 49.573 22.488 50.101 ;
     RECT  24 47.891 24.312 50.101 ;
     RECT  1.2 49.573 5.016 50.149 ;
     RECT  7.248 49.703 7.272 50.149 ;
     RECT  18.6 49.703 18.696 50.149 ;
     RECT  20.592 50.101 21.384 50.149 ;
     RECT  22.464 50.101 24.312 50.149 ;
     RECT  26.688 49.043 27.096 50.149 ;
     RECT  29.712 49.703 30.12 50.149 ;
     RECT  31.248 49.573 32.04 50.149 ;
     RECT  36.192 49.525 37.704 50.149 ;
     RECT  41.52 49.285 41.544 50.149 ;
     RECT  43.776 48.997 43.8 50.149 ;
     RECT  49.488 49.573 49.896 50.389 ;
     RECT  1.2 50.149 7.272 50.677 ;
     RECT  8.4 50.149 8.424 50.677 ;
     RECT  9.936 50.149 9.96 50.677 ;
     RECT  12.96 49.689 13.368 50.677 ;
     RECT  14.496 49.573 14.52 50.677 ;
     RECT  15.648 49.573 15.672 50.677 ;
     RECT  17.904 50.149 18.696 50.677 ;
     RECT  20.592 50.149 24.792 50.677 ;
     RECT  26.304 50.149 27.096 50.677 ;
     RECT  28.176 50.149 28.584 50.677 ;
     RECT  29.712 50.149 32.04 50.677 ;
     RECT  33.12 49.235 33.528 50.677 ;
     RECT  36.192 50.149 38.472 50.677 ;
     RECT  39.6 50.149 39.624 50.677 ;
     RECT  41.136 50.149 41.544 50.677 ;
     RECT  43.776 50.149 44.568 50.677 ;
     RECT  45.696 49.703 45.72 50.677 ;
     RECT  48.336 50.101 48.36 50.677 ;
     RECT  49.488 50.389 50.664 50.677 ;
     RECT  1.2 50.677 50.664 51.792 ;
  END
END ot_hbm_pc_refresh_cfg
END LIBRARY
